VERSION 5.8 ;
BUSBITCHARS "[]" ;
DIVIDERCHAR "/" ;
UNITS
    DATABASE MICRONS 1000 ;
END UNITS

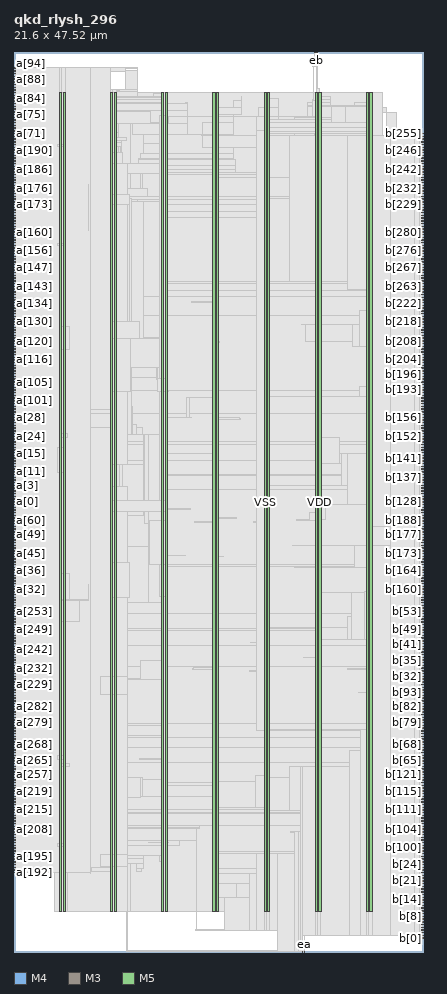
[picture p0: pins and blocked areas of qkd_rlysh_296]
MACRO qkd_rlysh_296
  FOREIGN qkd_rlysh_296 0 0 ;
  CLASS BLOCK ;
  SIZE 21.6 BY 47.52 ;
  PIN a[0]
    DIRECTION INPUT ;
    USE SIGNAL ;
    PORT
      LAYER M4 ;
        RECT  0 23.76 0.084 23.784 ;
    END
  END a[0]
  PIN a[100]
    DIRECTION INPUT ;
    USE SIGNAL ;
    PORT
      LAYER M4 ;
        RECT  0 28.944 0.084 28.968 ;
    END
  END a[100]
  PIN a[101]
    DIRECTION INPUT ;
    USE SIGNAL ;
    PORT
      LAYER M4 ;
        RECT  0 29.088 0.084 29.112 ;
    END
  END a[101]
  PIN a[102]
    DIRECTION INPUT ;
    USE SIGNAL ;
    PORT
      LAYER M4 ;
        RECT  0 29.232 0.084 29.256 ;
    END
  END a[102]
  PIN a[103]
    DIRECTION INPUT ;
    USE SIGNAL ;
    PORT
      LAYER M4 ;
        RECT  0 29.376 0.084 29.4 ;
    END
  END a[103]
  PIN a[104]
    DIRECTION INPUT ;
    USE SIGNAL ;
    PORT
      LAYER M4 ;
        RECT  0 29.52 0.084 29.544 ;
    END
  END a[104]
  PIN a[105]
    DIRECTION INPUT ;
    USE SIGNAL ;
    PORT
      LAYER M4 ;
        RECT  0 29.664 0.084 29.688 ;
    END
  END a[105]
  PIN a[106]
    DIRECTION INPUT ;
    USE SIGNAL ;
    PORT
      LAYER M4 ;
        RECT  0 29.808 0.084 29.832 ;
    END
  END a[106]
  PIN a[107]
    DIRECTION INPUT ;
    USE SIGNAL ;
    PORT
      LAYER M4 ;
        RECT  0 29.952 0.084 29.976 ;
    END
  END a[107]
  PIN a[108]
    DIRECTION INPUT ;
    USE SIGNAL ;
    PORT
      LAYER M4 ;
        RECT  0 30.096 0.084 30.12 ;
    END
  END a[108]
  PIN a[109]
    DIRECTION INPUT ;
    USE SIGNAL ;
    PORT
      LAYER M4 ;
        RECT  0 30.24 0.084 30.264 ;
    END
  END a[109]
  PIN a[10]
    DIRECTION INPUT ;
    USE SIGNAL ;
    PORT
      LAYER M4 ;
        RECT  0 25.2 0.084 25.224 ;
    END
  END a[10]
  PIN a[110]
    DIRECTION INPUT ;
    USE SIGNAL ;
    PORT
      LAYER M4 ;
        RECT  0 30.384 0.084 30.408 ;
    END
  END a[110]
  PIN a[111]
    DIRECTION INPUT ;
    USE SIGNAL ;
    PORT
      LAYER M4 ;
        RECT  0 30.528 0.084 30.552 ;
    END
  END a[111]
  PIN a[112]
    DIRECTION INPUT ;
    USE SIGNAL ;
    PORT
      LAYER M4 ;
        RECT  0 30.672 0.084 30.696 ;
    END
  END a[112]
  PIN a[113]
    DIRECTION INPUT ;
    USE SIGNAL ;
    PORT
      LAYER M4 ;
        RECT  0 30.816 0.084 30.84 ;
    END
  END a[113]
  PIN a[114]
    DIRECTION INPUT ;
    USE SIGNAL ;
    PORT
      LAYER M4 ;
        RECT  0 30.96 0.084 30.984 ;
    END
  END a[114]
  PIN a[115]
    DIRECTION INPUT ;
    USE SIGNAL ;
    PORT
      LAYER M4 ;
        RECT  0 31.104 0.084 31.128 ;
    END
  END a[115]
  PIN a[116]
    DIRECTION INPUT ;
    USE SIGNAL ;
    PORT
      LAYER M4 ;
        RECT  0 31.248 0.084 31.272 ;
    END
  END a[116]
  PIN a[117]
    DIRECTION INPUT ;
    USE SIGNAL ;
    PORT
      LAYER M4 ;
        RECT  0 31.392 0.084 31.416 ;
    END
  END a[117]
  PIN a[118]
    DIRECTION INPUT ;
    USE SIGNAL ;
    PORT
      LAYER M4 ;
        RECT  0 31.536 0.084 31.56 ;
    END
  END a[118]
  PIN a[119]
    DIRECTION INPUT ;
    USE SIGNAL ;
    PORT
      LAYER M4 ;
        RECT  0 31.68 0.084 31.704 ;
    END
  END a[119]
  PIN a[11]
    DIRECTION INPUT ;
    USE SIGNAL ;
    PORT
      LAYER M4 ;
        RECT  0 25.344 0.084 25.368 ;
    END
  END a[11]
  PIN a[120]
    DIRECTION INPUT ;
    USE SIGNAL ;
    PORT
      LAYER M4 ;
        RECT  0 31.824 0.084 31.848 ;
    END
  END a[120]
  PIN a[121]
    DIRECTION INPUT ;
    USE SIGNAL ;
    PORT
      LAYER M4 ;
        RECT  0 31.968 0.084 31.992 ;
    END
  END a[121]
  PIN a[122]
    DIRECTION INPUT ;
    USE SIGNAL ;
    PORT
      LAYER M4 ;
        RECT  0 32.112 0.084 32.136 ;
    END
  END a[122]
  PIN a[123]
    DIRECTION INPUT ;
    USE SIGNAL ;
    PORT
      LAYER M4 ;
        RECT  0 32.256 0.084 32.28 ;
    END
  END a[123]
  PIN a[124]
    DIRECTION INPUT ;
    USE SIGNAL ;
    PORT
      LAYER M4 ;
        RECT  0 32.4 0.084 32.424 ;
    END
  END a[124]
  PIN a[125]
    DIRECTION INPUT ;
    USE SIGNAL ;
    PORT
      LAYER M4 ;
        RECT  0 32.544 0.084 32.568 ;
    END
  END a[125]
  PIN a[126]
    DIRECTION INPUT ;
    USE SIGNAL ;
    PORT
      LAYER M4 ;
        RECT  0 32.688 0.084 32.712 ;
    END
  END a[126]
  PIN a[127]
    DIRECTION INPUT ;
    USE SIGNAL ;
    PORT
      LAYER M4 ;
        RECT  0 32.832 0.084 32.856 ;
    END
  END a[127]
  PIN a[128]
    DIRECTION INPUT ;
    USE SIGNAL ;
    PORT
      LAYER M4 ;
        RECT  0 32.976 0.084 33 ;
    END
  END a[128]
  PIN a[129]
    DIRECTION INPUT ;
    USE SIGNAL ;
    PORT
      LAYER M4 ;
        RECT  0 33.12 0.084 33.144 ;
    END
  END a[129]
  PIN a[12]
    DIRECTION INPUT ;
    USE SIGNAL ;
    PORT
      LAYER M4 ;
        RECT  0 25.488 0.084 25.512 ;
    END
  END a[12]
  PIN a[130]
    DIRECTION INPUT ;
    USE SIGNAL ;
    PORT
      LAYER M4 ;
        RECT  0 33.264 0.084 33.288 ;
    END
  END a[130]
  PIN a[131]
    DIRECTION INPUT ;
    USE SIGNAL ;
    PORT
      LAYER M4 ;
        RECT  0 33.408 0.084 33.432 ;
    END
  END a[131]
  PIN a[132]
    DIRECTION INPUT ;
    USE SIGNAL ;
    PORT
      LAYER M4 ;
        RECT  0 33.552 0.084 33.576 ;
    END
  END a[132]
  PIN a[133]
    DIRECTION INPUT ;
    USE SIGNAL ;
    PORT
      LAYER M4 ;
        RECT  0 33.696 0.084 33.72 ;
    END
  END a[133]
  PIN a[134]
    DIRECTION INPUT ;
    USE SIGNAL ;
    PORT
      LAYER M4 ;
        RECT  0 33.84 0.084 33.864 ;
    END
  END a[134]
  PIN a[135]
    DIRECTION INPUT ;
    USE SIGNAL ;
    PORT
      LAYER M4 ;
        RECT  0 33.984 0.084 34.008 ;
    END
  END a[135]
  PIN a[136]
    DIRECTION INPUT ;
    USE SIGNAL ;
    PORT
      LAYER M4 ;
        RECT  0 34.128 0.084 34.152 ;
    END
  END a[136]
  PIN a[137]
    DIRECTION INPUT ;
    USE SIGNAL ;
    PORT
      LAYER M4 ;
        RECT  0 34.272 0.084 34.296 ;
    END
  END a[137]
  PIN a[138]
    DIRECTION INPUT ;
    USE SIGNAL ;
    PORT
      LAYER M4 ;
        RECT  0 34.416 0.084 34.44 ;
    END
  END a[138]
  PIN a[139]
    DIRECTION INPUT ;
    USE SIGNAL ;
    PORT
      LAYER M4 ;
        RECT  0 34.56 0.084 34.584 ;
    END
  END a[139]
  PIN a[13]
    DIRECTION INPUT ;
    USE SIGNAL ;
    PORT
      LAYER M4 ;
        RECT  0 25.632 0.084 25.656 ;
    END
  END a[13]
  PIN a[140]
    DIRECTION INPUT ;
    USE SIGNAL ;
    PORT
      LAYER M4 ;
        RECT  0 34.704 0.084 34.728 ;
    END
  END a[140]
  PIN a[141]
    DIRECTION INPUT ;
    USE SIGNAL ;
    PORT
      LAYER M4 ;
        RECT  0 34.848 0.084 34.872 ;
    END
  END a[141]
  PIN a[142]
    DIRECTION INPUT ;
    USE SIGNAL ;
    PORT
      LAYER M4 ;
        RECT  0 34.992 0.084 35.016 ;
    END
  END a[142]
  PIN a[143]
    DIRECTION INPUT ;
    USE SIGNAL ;
    PORT
      LAYER M4 ;
        RECT  0 35.136 0.084 35.16 ;
    END
  END a[143]
  PIN a[144]
    DIRECTION INPUT ;
    USE SIGNAL ;
    PORT
      LAYER M4 ;
        RECT  0 35.28 0.084 35.304 ;
    END
  END a[144]
  PIN a[145]
    DIRECTION INPUT ;
    USE SIGNAL ;
    PORT
      LAYER M4 ;
        RECT  0 35.424 0.084 35.448 ;
    END
  END a[145]
  PIN a[146]
    DIRECTION INPUT ;
    USE SIGNAL ;
    PORT
      LAYER M4 ;
        RECT  0 35.568 0.084 35.592 ;
    END
  END a[146]
  PIN a[147]
    DIRECTION INPUT ;
    USE SIGNAL ;
    PORT
      LAYER M4 ;
        RECT  0 35.712 0.084 35.736 ;
    END
  END a[147]
  PIN a[148]
    DIRECTION INPUT ;
    USE SIGNAL ;
    PORT
      LAYER M4 ;
        RECT  0 35.856 0.084 35.88 ;
    END
  END a[148]
  PIN a[149]
    DIRECTION INPUT ;
    USE SIGNAL ;
    PORT
      LAYER M4 ;
        RECT  0 36 0.084 36.024 ;
    END
  END a[149]
  PIN a[14]
    DIRECTION INPUT ;
    USE SIGNAL ;
    PORT
      LAYER M4 ;
        RECT  0 25.776 0.084 25.8 ;
    END
  END a[14]
  PIN a[150]
    DIRECTION INPUT ;
    USE SIGNAL ;
    PORT
      LAYER M4 ;
        RECT  0 36.144 0.084 36.168 ;
    END
  END a[150]
  PIN a[151]
    DIRECTION INPUT ;
    USE SIGNAL ;
    PORT
      LAYER M4 ;
        RECT  0 36.288 0.084 36.312 ;
    END
  END a[151]
  PIN a[152]
    DIRECTION INPUT ;
    USE SIGNAL ;
    PORT
      LAYER M4 ;
        RECT  0 36.432 0.084 36.456 ;
    END
  END a[152]
  PIN a[153]
    DIRECTION INPUT ;
    USE SIGNAL ;
    PORT
      LAYER M4 ;
        RECT  0 36.576 0.084 36.6 ;
    END
  END a[153]
  PIN a[154]
    DIRECTION INPUT ;
    USE SIGNAL ;
    PORT
      LAYER M4 ;
        RECT  0 36.72 0.084 36.744 ;
    END
  END a[154]
  PIN a[155]
    DIRECTION INPUT ;
    USE SIGNAL ;
    PORT
      LAYER M4 ;
        RECT  0 36.864 0.084 36.888 ;
    END
  END a[155]
  PIN a[156]
    DIRECTION INPUT ;
    USE SIGNAL ;
    PORT
      LAYER M4 ;
        RECT  0 37.008 0.084 37.032 ;
    END
  END a[156]
  PIN a[157]
    DIRECTION INPUT ;
    USE SIGNAL ;
    PORT
      LAYER M4 ;
        RECT  0 37.152 0.084 37.176 ;
    END
  END a[157]
  PIN a[158]
    DIRECTION INPUT ;
    USE SIGNAL ;
    PORT
      LAYER M4 ;
        RECT  0 37.296 0.084 37.32 ;
    END
  END a[158]
  PIN a[159]
    DIRECTION INPUT ;
    USE SIGNAL ;
    PORT
      LAYER M4 ;
        RECT  0 37.44 0.084 37.464 ;
    END
  END a[159]
  PIN a[15]
    DIRECTION INPUT ;
    USE SIGNAL ;
    PORT
      LAYER M4 ;
        RECT  0 25.92 0.084 25.944 ;
    END
  END a[15]
  PIN a[160]
    DIRECTION INPUT ;
    USE SIGNAL ;
    PORT
      LAYER M4 ;
        RECT  0 37.584 0.084 37.608 ;
    END
  END a[160]
  PIN a[161]
    DIRECTION INPUT ;
    USE SIGNAL ;
    PORT
      LAYER M4 ;
        RECT  0 37.728 0.084 37.752 ;
    END
  END a[161]
  PIN a[162]
    DIRECTION INPUT ;
    USE SIGNAL ;
    PORT
      LAYER M4 ;
        RECT  0 37.872 0.084 37.896 ;
    END
  END a[162]
  PIN a[163]
    DIRECTION INPUT ;
    USE SIGNAL ;
    PORT
      LAYER M4 ;
        RECT  0 38.016 0.084 38.04 ;
    END
  END a[163]
  PIN a[164]
    DIRECTION INPUT ;
    USE SIGNAL ;
    PORT
      LAYER M4 ;
        RECT  0 38.16 0.084 38.184 ;
    END
  END a[164]
  PIN a[165]
    DIRECTION INPUT ;
    USE SIGNAL ;
    PORT
      LAYER M4 ;
        RECT  0 38.304 0.084 38.328 ;
    END
  END a[165]
  PIN a[166]
    DIRECTION INPUT ;
    USE SIGNAL ;
    PORT
      LAYER M4 ;
        RECT  0 38.448 0.084 38.472 ;
    END
  END a[166]
  PIN a[167]
    DIRECTION INPUT ;
    USE SIGNAL ;
    PORT
      LAYER M4 ;
        RECT  0 38.592 0.084 38.616 ;
    END
  END a[167]
  PIN a[168]
    DIRECTION INPUT ;
    USE SIGNAL ;
    PORT
      LAYER M4 ;
        RECT  0 38.736 0.084 38.76 ;
    END
  END a[168]
  PIN a[169]
    DIRECTION INPUT ;
    USE SIGNAL ;
    PORT
      LAYER M4 ;
        RECT  0 38.88 0.084 38.904 ;
    END
  END a[169]
  PIN a[16]
    DIRECTION INPUT ;
    USE SIGNAL ;
    PORT
      LAYER M4 ;
        RECT  0 26.064 0.084 26.088 ;
    END
  END a[16]
  PIN a[170]
    DIRECTION INPUT ;
    USE SIGNAL ;
    PORT
      LAYER M4 ;
        RECT  0 39.024 0.084 39.048 ;
    END
  END a[170]
  PIN a[171]
    DIRECTION INPUT ;
    USE SIGNAL ;
    PORT
      LAYER M4 ;
        RECT  0 39.168 0.084 39.192 ;
    END
  END a[171]
  PIN a[172]
    DIRECTION INPUT ;
    USE SIGNAL ;
    PORT
      LAYER M4 ;
        RECT  0 39.312 0.084 39.336 ;
    END
  END a[172]
  PIN a[173]
    DIRECTION INPUT ;
    USE SIGNAL ;
    PORT
      LAYER M4 ;
        RECT  0 39.456 0.084 39.48 ;
    END
  END a[173]
  PIN a[174]
    DIRECTION INPUT ;
    USE SIGNAL ;
    PORT
      LAYER M4 ;
        RECT  0 39.6 0.084 39.624 ;
    END
  END a[174]
  PIN a[175]
    DIRECTION INPUT ;
    USE SIGNAL ;
    PORT
      LAYER M4 ;
        RECT  0 39.744 0.084 39.768 ;
    END
  END a[175]
  PIN a[176]
    DIRECTION INPUT ;
    USE SIGNAL ;
    PORT
      LAYER M4 ;
        RECT  0 39.888 0.084 39.912 ;
    END
  END a[176]
  PIN a[177]
    DIRECTION INPUT ;
    USE SIGNAL ;
    PORT
      LAYER M4 ;
        RECT  0 40.032 0.084 40.056 ;
    END
  END a[177]
  PIN a[178]
    DIRECTION INPUT ;
    USE SIGNAL ;
    PORT
      LAYER M4 ;
        RECT  0 40.176 0.084 40.2 ;
    END
  END a[178]
  PIN a[179]
    DIRECTION INPUT ;
    USE SIGNAL ;
    PORT
      LAYER M4 ;
        RECT  0 40.32 0.084 40.344 ;
    END
  END a[179]
  PIN a[17]
    DIRECTION INPUT ;
    USE SIGNAL ;
    PORT
      LAYER M4 ;
        RECT  0 26.208 0.084 26.232 ;
    END
  END a[17]
  PIN a[180]
    DIRECTION INPUT ;
    USE SIGNAL ;
    PORT
      LAYER M4 ;
        RECT  0 40.464 0.084 40.488 ;
    END
  END a[180]
  PIN a[181]
    DIRECTION INPUT ;
    USE SIGNAL ;
    PORT
      LAYER M4 ;
        RECT  0 40.608 0.084 40.632 ;
    END
  END a[181]
  PIN a[182]
    DIRECTION INPUT ;
    USE SIGNAL ;
    PORT
      LAYER M4 ;
        RECT  0 40.752 0.084 40.776 ;
    END
  END a[182]
  PIN a[183]
    DIRECTION INPUT ;
    USE SIGNAL ;
    PORT
      LAYER M4 ;
        RECT  0 40.896 0.084 40.92 ;
    END
  END a[183]
  PIN a[184]
    DIRECTION INPUT ;
    USE SIGNAL ;
    PORT
      LAYER M4 ;
        RECT  0 41.04 0.084 41.064 ;
    END
  END a[184]
  PIN a[185]
    DIRECTION INPUT ;
    USE SIGNAL ;
    PORT
      LAYER M4 ;
        RECT  0 41.184 0.084 41.208 ;
    END
  END a[185]
  PIN a[186]
    DIRECTION INPUT ;
    USE SIGNAL ;
    PORT
      LAYER M4 ;
        RECT  0 41.328 0.084 41.352 ;
    END
  END a[186]
  PIN a[187]
    DIRECTION INPUT ;
    USE SIGNAL ;
    PORT
      LAYER M4 ;
        RECT  0 41.472 0.084 41.496 ;
    END
  END a[187]
  PIN a[188]
    DIRECTION INPUT ;
    USE SIGNAL ;
    PORT
      LAYER M4 ;
        RECT  0 41.616 0.084 41.64 ;
    END
  END a[188]
  PIN a[189]
    DIRECTION INPUT ;
    USE SIGNAL ;
    PORT
      LAYER M4 ;
        RECT  0 41.76 0.084 41.784 ;
    END
  END a[189]
  PIN a[18]
    DIRECTION INPUT ;
    USE SIGNAL ;
    PORT
      LAYER M4 ;
        RECT  0 26.352 0.084 26.376 ;
    END
  END a[18]
  PIN a[190]
    DIRECTION INPUT ;
    USE SIGNAL ;
    PORT
      LAYER M4 ;
        RECT  0 41.904 0.084 41.928 ;
    END
  END a[190]
  PIN a[191]
    DIRECTION INPUT ;
    USE SIGNAL ;
    PORT
      LAYER M4 ;
        RECT  0 42.048 0.084 42.072 ;
    END
  END a[191]
  PIN a[192]
    DIRECTION INPUT ;
    USE SIGNAL ;
    PORT
      LAYER M4 ;
        RECT  0 4.176 0.084 4.2 ;
    END
  END a[192]
  PIN a[193]
    DIRECTION INPUT ;
    USE SIGNAL ;
    PORT
      LAYER M4 ;
        RECT  0 4.32 0.084 4.344 ;
    END
  END a[193]
  PIN a[194]
    DIRECTION INPUT ;
    USE SIGNAL ;
    PORT
      LAYER M4 ;
        RECT  0 4.464 0.084 4.488 ;
    END
  END a[194]
  PIN a[195]
    DIRECTION INPUT ;
    USE SIGNAL ;
    PORT
      LAYER M4 ;
        RECT  0 4.608 0.084 4.632 ;
    END
  END a[195]
  PIN a[196]
    DIRECTION INPUT ;
    USE SIGNAL ;
    PORT
      LAYER M4 ;
        RECT  0 4.752 0.084 4.776 ;
    END
  END a[196]
  PIN a[197]
    DIRECTION INPUT ;
    USE SIGNAL ;
    PORT
      LAYER M4 ;
        RECT  0 4.896 0.084 4.92 ;
    END
  END a[197]
  PIN a[198]
    DIRECTION INPUT ;
    USE SIGNAL ;
    PORT
      LAYER M4 ;
        RECT  0 5.04 0.084 5.064 ;
    END
  END a[198]
  PIN a[199]
    DIRECTION INPUT ;
    USE SIGNAL ;
    PORT
      LAYER M4 ;
        RECT  0 5.184 0.084 5.208 ;
    END
  END a[199]
  PIN a[19]
    DIRECTION INPUT ;
    USE SIGNAL ;
    PORT
      LAYER M4 ;
        RECT  0 26.496 0.084 26.52 ;
    END
  END a[19]
  PIN a[1]
    DIRECTION INPUT ;
    USE SIGNAL ;
    PORT
      LAYER M4 ;
        RECT  0 23.904 0.084 23.928 ;
    END
  END a[1]
  PIN a[200]
    DIRECTION INPUT ;
    USE SIGNAL ;
    PORT
      LAYER M4 ;
        RECT  0 5.328 0.084 5.352 ;
    END
  END a[200]
  PIN a[201]
    DIRECTION INPUT ;
    USE SIGNAL ;
    PORT
      LAYER M4 ;
        RECT  0 5.472 0.084 5.496 ;
    END
  END a[201]
  PIN a[202]
    DIRECTION INPUT ;
    USE SIGNAL ;
    PORT
      LAYER M4 ;
        RECT  0 5.616 0.084 5.64 ;
    END
  END a[202]
  PIN a[203]
    DIRECTION INPUT ;
    USE SIGNAL ;
    PORT
      LAYER M4 ;
        RECT  0 5.76 0.084 5.784 ;
    END
  END a[203]
  PIN a[204]
    DIRECTION INPUT ;
    USE SIGNAL ;
    PORT
      LAYER M4 ;
        RECT  0 5.904 0.084 5.928 ;
    END
  END a[204]
  PIN a[205]
    DIRECTION INPUT ;
    USE SIGNAL ;
    PORT
      LAYER M4 ;
        RECT  0 6.048 0.084 6.072 ;
    END
  END a[205]
  PIN a[206]
    DIRECTION INPUT ;
    USE SIGNAL ;
    PORT
      LAYER M4 ;
        RECT  0 6.192 0.084 6.216 ;
    END
  END a[206]
  PIN a[207]
    DIRECTION INPUT ;
    USE SIGNAL ;
    PORT
      LAYER M4 ;
        RECT  0 6.336 0.084 6.36 ;
    END
  END a[207]
  PIN a[208]
    DIRECTION INPUT ;
    USE SIGNAL ;
    PORT
      LAYER M4 ;
        RECT  0 6.48 0.084 6.504 ;
    END
  END a[208]
  PIN a[209]
    DIRECTION INPUT ;
    USE SIGNAL ;
    PORT
      LAYER M4 ;
        RECT  0 6.624 0.084 6.648 ;
    END
  END a[209]
  PIN a[20]
    DIRECTION INPUT ;
    USE SIGNAL ;
    PORT
      LAYER M4 ;
        RECT  0 26.64 0.084 26.664 ;
    END
  END a[20]
  PIN a[210]
    DIRECTION INPUT ;
    USE SIGNAL ;
    PORT
      LAYER M4 ;
        RECT  0 6.768 0.084 6.792 ;
    END
  END a[210]
  PIN a[211]
    DIRECTION INPUT ;
    USE SIGNAL ;
    PORT
      LAYER M4 ;
        RECT  0 6.912 0.084 6.936 ;
    END
  END a[211]
  PIN a[212]
    DIRECTION INPUT ;
    USE SIGNAL ;
    PORT
      LAYER M4 ;
        RECT  0 7.056 0.084 7.08 ;
    END
  END a[212]
  PIN a[213]
    DIRECTION INPUT ;
    USE SIGNAL ;
    PORT
      LAYER M4 ;
        RECT  0 7.2 0.084 7.224 ;
    END
  END a[213]
  PIN a[214]
    DIRECTION INPUT ;
    USE SIGNAL ;
    PORT
      LAYER M4 ;
        RECT  0 7.344 0.084 7.368 ;
    END
  END a[214]
  PIN a[215]
    DIRECTION INPUT ;
    USE SIGNAL ;
    PORT
      LAYER M4 ;
        RECT  0 7.488 0.084 7.512 ;
    END
  END a[215]
  PIN a[216]
    DIRECTION INPUT ;
    USE SIGNAL ;
    PORT
      LAYER M4 ;
        RECT  0 7.632 0.084 7.656 ;
    END
  END a[216]
  PIN a[217]
    DIRECTION INPUT ;
    USE SIGNAL ;
    PORT
      LAYER M4 ;
        RECT  0 7.776 0.084 7.8 ;
    END
  END a[217]
  PIN a[218]
    DIRECTION INPUT ;
    USE SIGNAL ;
    PORT
      LAYER M4 ;
        RECT  0 7.92 0.084 7.944 ;
    END
  END a[218]
  PIN a[219]
    DIRECTION INPUT ;
    USE SIGNAL ;
    PORT
      LAYER M4 ;
        RECT  0 8.064 0.084 8.088 ;
    END
  END a[219]
  PIN a[21]
    DIRECTION INPUT ;
    USE SIGNAL ;
    PORT
      LAYER M4 ;
        RECT  0 26.784 0.084 26.808 ;
    END
  END a[21]
  PIN a[220]
    DIRECTION INPUT ;
    USE SIGNAL ;
    PORT
      LAYER M4 ;
        RECT  0 8.208 0.084 8.232 ;
    END
  END a[220]
  PIN a[221]
    DIRECTION INPUT ;
    USE SIGNAL ;
    PORT
      LAYER M4 ;
        RECT  0 8.352 0.084 8.376 ;
    END
  END a[221]
  PIN a[222]
    DIRECTION INPUT ;
    USE SIGNAL ;
    PORT
      LAYER M4 ;
        RECT  0 8.496 0.084 8.52 ;
    END
  END a[222]
  PIN a[223]
    DIRECTION INPUT ;
    USE SIGNAL ;
    PORT
      LAYER M4 ;
        RECT  0 8.64 0.084 8.664 ;
    END
  END a[223]
  PIN a[224]
    DIRECTION INPUT ;
    USE SIGNAL ;
    PORT
      LAYER M4 ;
        RECT  0 13.392 0.084 13.416 ;
    END
  END a[224]
  PIN a[225]
    DIRECTION INPUT ;
    USE SIGNAL ;
    PORT
      LAYER M4 ;
        RECT  0 13.536 0.084 13.56 ;
    END
  END a[225]
  PIN a[226]
    DIRECTION INPUT ;
    USE SIGNAL ;
    PORT
      LAYER M4 ;
        RECT  0 13.68 0.084 13.704 ;
    END
  END a[226]
  PIN a[227]
    DIRECTION INPUT ;
    USE SIGNAL ;
    PORT
      LAYER M4 ;
        RECT  0 13.824 0.084 13.848 ;
    END
  END a[227]
  PIN a[228]
    DIRECTION INPUT ;
    USE SIGNAL ;
    PORT
      LAYER M4 ;
        RECT  0 13.968 0.084 13.992 ;
    END
  END a[228]
  PIN a[229]
    DIRECTION INPUT ;
    USE SIGNAL ;
    PORT
      LAYER M4 ;
        RECT  0 14.112 0.084 14.136 ;
    END
  END a[229]
  PIN a[22]
    DIRECTION INPUT ;
    USE SIGNAL ;
    PORT
      LAYER M4 ;
        RECT  0 26.928 0.084 26.952 ;
    END
  END a[22]
  PIN a[230]
    DIRECTION INPUT ;
    USE SIGNAL ;
    PORT
      LAYER M4 ;
        RECT  0 14.256 0.084 14.28 ;
    END
  END a[230]
  PIN a[231]
    DIRECTION INPUT ;
    USE SIGNAL ;
    PORT
      LAYER M4 ;
        RECT  0 14.4 0.084 14.424 ;
    END
  END a[231]
  PIN a[232]
    DIRECTION INPUT ;
    USE SIGNAL ;
    PORT
      LAYER M4 ;
        RECT  0 14.544 0.084 14.568 ;
    END
  END a[232]
  PIN a[233]
    DIRECTION INPUT ;
    USE SIGNAL ;
    PORT
      LAYER M4 ;
        RECT  0 14.688 0.084 14.712 ;
    END
  END a[233]
  PIN a[234]
    DIRECTION INPUT ;
    USE SIGNAL ;
    PORT
      LAYER M4 ;
        RECT  0 14.832 0.084 14.856 ;
    END
  END a[234]
  PIN a[235]
    DIRECTION INPUT ;
    USE SIGNAL ;
    PORT
      LAYER M4 ;
        RECT  0 14.976 0.084 15 ;
    END
  END a[235]
  PIN a[236]
    DIRECTION INPUT ;
    USE SIGNAL ;
    PORT
      LAYER M4 ;
        RECT  0 15.12 0.084 15.144 ;
    END
  END a[236]
  PIN a[237]
    DIRECTION INPUT ;
    USE SIGNAL ;
    PORT
      LAYER M4 ;
        RECT  0 15.264 0.084 15.288 ;
    END
  END a[237]
  PIN a[238]
    DIRECTION INPUT ;
    USE SIGNAL ;
    PORT
      LAYER M4 ;
        RECT  0 15.408 0.084 15.432 ;
    END
  END a[238]
  PIN a[239]
    DIRECTION INPUT ;
    USE SIGNAL ;
    PORT
      LAYER M4 ;
        RECT  0 15.552 0.084 15.576 ;
    END
  END a[239]
  PIN a[23]
    DIRECTION INPUT ;
    USE SIGNAL ;
    PORT
      LAYER M4 ;
        RECT  0 27.072 0.084 27.096 ;
    END
  END a[23]
  PIN a[240]
    DIRECTION INPUT ;
    USE SIGNAL ;
    PORT
      LAYER M4 ;
        RECT  0 15.696 0.084 15.72 ;
    END
  END a[240]
  PIN a[241]
    DIRECTION INPUT ;
    USE SIGNAL ;
    PORT
      LAYER M4 ;
        RECT  0 15.84 0.084 15.864 ;
    END
  END a[241]
  PIN a[242]
    DIRECTION INPUT ;
    USE SIGNAL ;
    PORT
      LAYER M4 ;
        RECT  0 15.984 0.084 16.008 ;
    END
  END a[242]
  PIN a[243]
    DIRECTION INPUT ;
    USE SIGNAL ;
    PORT
      LAYER M4 ;
        RECT  0 16.128 0.084 16.152 ;
    END
  END a[243]
  PIN a[244]
    DIRECTION INPUT ;
    USE SIGNAL ;
    PORT
      LAYER M4 ;
        RECT  0 16.272 0.084 16.296 ;
    END
  END a[244]
  PIN a[245]
    DIRECTION INPUT ;
    USE SIGNAL ;
    PORT
      LAYER M4 ;
        RECT  0 16.416 0.084 16.44 ;
    END
  END a[245]
  PIN a[246]
    DIRECTION INPUT ;
    USE SIGNAL ;
    PORT
      LAYER M4 ;
        RECT  0 16.56 0.084 16.584 ;
    END
  END a[246]
  PIN a[247]
    DIRECTION INPUT ;
    USE SIGNAL ;
    PORT
      LAYER M4 ;
        RECT  0 16.704 0.084 16.728 ;
    END
  END a[247]
  PIN a[248]
    DIRECTION INPUT ;
    USE SIGNAL ;
    PORT
      LAYER M4 ;
        RECT  0 16.848 0.084 16.872 ;
    END
  END a[248]
  PIN a[249]
    DIRECTION INPUT ;
    USE SIGNAL ;
    PORT
      LAYER M4 ;
        RECT  0 16.992 0.084 17.016 ;
    END
  END a[249]
  PIN a[24]
    DIRECTION INPUT ;
    USE SIGNAL ;
    PORT
      LAYER M4 ;
        RECT  0 27.216 0.084 27.24 ;
    END
  END a[24]
  PIN a[250]
    DIRECTION INPUT ;
    USE SIGNAL ;
    PORT
      LAYER M4 ;
        RECT  0 17.136 0.084 17.16 ;
    END
  END a[250]
  PIN a[251]
    DIRECTION INPUT ;
    USE SIGNAL ;
    PORT
      LAYER M4 ;
        RECT  0 17.28 0.084 17.304 ;
    END
  END a[251]
  PIN a[252]
    DIRECTION INPUT ;
    USE SIGNAL ;
    PORT
      LAYER M4 ;
        RECT  0 17.424 0.084 17.448 ;
    END
  END a[252]
  PIN a[253]
    DIRECTION INPUT ;
    USE SIGNAL ;
    PORT
      LAYER M4 ;
        RECT  0 17.568 0.084 17.592 ;
    END
  END a[253]
  PIN a[254]
    DIRECTION INPUT ;
    USE SIGNAL ;
    PORT
      LAYER M4 ;
        RECT  0 17.712 0.084 17.736 ;
    END
  END a[254]
  PIN a[255]
    DIRECTION INPUT ;
    USE SIGNAL ;
    PORT
      LAYER M4 ;
        RECT  0 17.856 0.084 17.88 ;
    END
  END a[255]
  PIN a[256]
    DIRECTION INPUT ;
    USE SIGNAL ;
    PORT
      LAYER M4 ;
        RECT  0 8.784 0.084 8.808 ;
    END
  END a[256]
  PIN a[257]
    DIRECTION INPUT ;
    USE SIGNAL ;
    PORT
      LAYER M4 ;
        RECT  0 8.928 0.084 8.952 ;
    END
  END a[257]
  PIN a[258]
    DIRECTION INPUT ;
    USE SIGNAL ;
    PORT
      LAYER M4 ;
        RECT  0 9.072 0.084 9.096 ;
    END
  END a[258]
  PIN a[259]
    DIRECTION INPUT ;
    USE SIGNAL ;
    PORT
      LAYER M4 ;
        RECT  0 9.216 0.084 9.24 ;
    END
  END a[259]
  PIN a[25]
    DIRECTION INPUT ;
    USE SIGNAL ;
    PORT
      LAYER M4 ;
        RECT  0 27.36 0.084 27.384 ;
    END
  END a[25]
  PIN a[260]
    DIRECTION INPUT ;
    USE SIGNAL ;
    PORT
      LAYER M4 ;
        RECT  0 9.36 0.084 9.384 ;
    END
  END a[260]
  PIN a[261]
    DIRECTION INPUT ;
    USE SIGNAL ;
    PORT
      LAYER M4 ;
        RECT  0 9.504 0.084 9.528 ;
    END
  END a[261]
  PIN a[262]
    DIRECTION INPUT ;
    USE SIGNAL ;
    PORT
      LAYER M4 ;
        RECT  0 9.648 0.084 9.672 ;
    END
  END a[262]
  PIN a[263]
    DIRECTION INPUT ;
    USE SIGNAL ;
    PORT
      LAYER M4 ;
        RECT  0 9.792 0.084 9.816 ;
    END
  END a[263]
  PIN a[264]
    DIRECTION INPUT ;
    USE SIGNAL ;
    PORT
      LAYER M4 ;
        RECT  0 9.936 0.084 9.96 ;
    END
  END a[264]
  PIN a[265]
    DIRECTION INPUT ;
    USE SIGNAL ;
    PORT
      LAYER M4 ;
        RECT  0 10.08 0.084 10.104 ;
    END
  END a[265]
  PIN a[266]
    DIRECTION INPUT ;
    USE SIGNAL ;
    PORT
      LAYER M4 ;
        RECT  0 10.224 0.084 10.248 ;
    END
  END a[266]
  PIN a[267]
    DIRECTION INPUT ;
    USE SIGNAL ;
    PORT
      LAYER M4 ;
        RECT  0 10.368 0.084 10.392 ;
    END
  END a[267]
  PIN a[268]
    DIRECTION INPUT ;
    USE SIGNAL ;
    PORT
      LAYER M4 ;
        RECT  0 10.512 0.084 10.536 ;
    END
  END a[268]
  PIN a[269]
    DIRECTION INPUT ;
    USE SIGNAL ;
    PORT
      LAYER M4 ;
        RECT  0 10.656 0.084 10.68 ;
    END
  END a[269]
  PIN a[26]
    DIRECTION INPUT ;
    USE SIGNAL ;
    PORT
      LAYER M4 ;
        RECT  0 27.504 0.084 27.528 ;
    END
  END a[26]
  PIN a[270]
    DIRECTION INPUT ;
    USE SIGNAL ;
    PORT
      LAYER M4 ;
        RECT  0 10.8 0.084 10.824 ;
    END
  END a[270]
  PIN a[271]
    DIRECTION INPUT ;
    USE SIGNAL ;
    PORT
      LAYER M4 ;
        RECT  0 10.944 0.084 10.968 ;
    END
  END a[271]
  PIN a[272]
    DIRECTION INPUT ;
    USE SIGNAL ;
    PORT
      LAYER M4 ;
        RECT  0 11.088 0.084 11.112 ;
    END
  END a[272]
  PIN a[273]
    DIRECTION INPUT ;
    USE SIGNAL ;
    PORT
      LAYER M4 ;
        RECT  0 11.232 0.084 11.256 ;
    END
  END a[273]
  PIN a[274]
    DIRECTION INPUT ;
    USE SIGNAL ;
    PORT
      LAYER M4 ;
        RECT  0 11.376 0.084 11.4 ;
    END
  END a[274]
  PIN a[275]
    DIRECTION INPUT ;
    USE SIGNAL ;
    PORT
      LAYER M4 ;
        RECT  0 11.52 0.084 11.544 ;
    END
  END a[275]
  PIN a[276]
    DIRECTION INPUT ;
    USE SIGNAL ;
    PORT
      LAYER M4 ;
        RECT  0 11.664 0.084 11.688 ;
    END
  END a[276]
  PIN a[277]
    DIRECTION INPUT ;
    USE SIGNAL ;
    PORT
      LAYER M4 ;
        RECT  0 11.808 0.084 11.832 ;
    END
  END a[277]
  PIN a[278]
    DIRECTION INPUT ;
    USE SIGNAL ;
    PORT
      LAYER M4 ;
        RECT  0 11.952 0.084 11.976 ;
    END
  END a[278]
  PIN a[279]
    DIRECTION INPUT ;
    USE SIGNAL ;
    PORT
      LAYER M4 ;
        RECT  0 12.096 0.084 12.12 ;
    END
  END a[279]
  PIN a[27]
    DIRECTION INPUT ;
    USE SIGNAL ;
    PORT
      LAYER M4 ;
        RECT  0 27.648 0.084 27.672 ;
    END
  END a[27]
  PIN a[280]
    DIRECTION INPUT ;
    USE SIGNAL ;
    PORT
      LAYER M4 ;
        RECT  0 12.24 0.084 12.264 ;
    END
  END a[280]
  PIN a[281]
    DIRECTION INPUT ;
    USE SIGNAL ;
    PORT
      LAYER M4 ;
        RECT  0 12.384 0.084 12.408 ;
    END
  END a[281]
  PIN a[282]
    DIRECTION INPUT ;
    USE SIGNAL ;
    PORT
      LAYER M4 ;
        RECT  0 12.528 0.084 12.552 ;
    END
  END a[282]
  PIN a[283]
    DIRECTION INPUT ;
    USE SIGNAL ;
    PORT
      LAYER M4 ;
        RECT  0 12.672 0.084 12.696 ;
    END
  END a[283]
  PIN a[284]
    DIRECTION INPUT ;
    USE SIGNAL ;
    PORT
      LAYER M4 ;
        RECT  0 12.816 0.084 12.84 ;
    END
  END a[284]
  PIN a[285]
    DIRECTION INPUT ;
    USE SIGNAL ;
    PORT
      LAYER M4 ;
        RECT  0 12.96 0.084 12.984 ;
    END
  END a[285]
  PIN a[286]
    DIRECTION INPUT ;
    USE SIGNAL ;
    PORT
      LAYER M4 ;
        RECT  0 13.104 0.084 13.128 ;
    END
  END a[286]
  PIN a[287]
    DIRECTION INPUT ;
    USE SIGNAL ;
    PORT
      LAYER M4 ;
        RECT  0 13.248 0.084 13.272 ;
    END
  END a[287]
  PIN a[288]
    DIRECTION INPUT ;
    USE SIGNAL ;
    PORT
      LAYER M4 ;
        RECT  0 18 0.084 18.024 ;
    END
  END a[288]
  PIN a[289]
    DIRECTION INPUT ;
    USE SIGNAL ;
    PORT
      LAYER M4 ;
        RECT  0 18.144 0.084 18.168 ;
    END
  END a[289]
  PIN a[28]
    DIRECTION INPUT ;
    USE SIGNAL ;
    PORT
      LAYER M4 ;
        RECT  0 27.792 0.084 27.816 ;
    END
  END a[28]
  PIN a[290]
    DIRECTION INPUT ;
    USE SIGNAL ;
    PORT
      LAYER M4 ;
        RECT  0 18.288 0.084 18.312 ;
    END
  END a[290]
  PIN a[291]
    DIRECTION INPUT ;
    USE SIGNAL ;
    PORT
      LAYER M4 ;
        RECT  0 18.432 0.084 18.456 ;
    END
  END a[291]
  PIN a[292]
    DIRECTION INPUT ;
    USE SIGNAL ;
    PORT
      LAYER M4 ;
        RECT  0 18.576 0.084 18.6 ;
    END
  END a[292]
  PIN a[293]
    DIRECTION INPUT ;
    USE SIGNAL ;
    PORT
      LAYER M4 ;
        RECT  0 18.72 0.084 18.744 ;
    END
  END a[293]
  PIN a[294]
    DIRECTION INPUT ;
    USE SIGNAL ;
    PORT
      LAYER M4 ;
        RECT  0 18.864 0.084 18.888 ;
    END
  END a[294]
  PIN a[295]
    DIRECTION INPUT ;
    USE SIGNAL ;
    PORT
      LAYER M4 ;
        RECT  0 19.008 0.084 19.032 ;
    END
  END a[295]
  PIN a[29]
    DIRECTION INPUT ;
    USE SIGNAL ;
    PORT
      LAYER M4 ;
        RECT  0 27.936 0.084 27.96 ;
    END
  END a[29]
  PIN a[2]
    DIRECTION INPUT ;
    USE SIGNAL ;
    PORT
      LAYER M4 ;
        RECT  0 24.048 0.084 24.072 ;
    END
  END a[2]
  PIN a[30]
    DIRECTION INPUT ;
    USE SIGNAL ;
    PORT
      LAYER M4 ;
        RECT  0 28.08 0.084 28.104 ;
    END
  END a[30]
  PIN a[31]
    DIRECTION INPUT ;
    USE SIGNAL ;
    PORT
      LAYER M4 ;
        RECT  0 28.224 0.084 28.248 ;
    END
  END a[31]
  PIN a[32]
    DIRECTION INPUT ;
    USE SIGNAL ;
    PORT
      LAYER M4 ;
        RECT  0 19.152 0.084 19.176 ;
    END
  END a[32]
  PIN a[33]
    DIRECTION INPUT ;
    USE SIGNAL ;
    PORT
      LAYER M4 ;
        RECT  0 19.296 0.084 19.32 ;
    END
  END a[33]
  PIN a[34]
    DIRECTION INPUT ;
    USE SIGNAL ;
    PORT
      LAYER M4 ;
        RECT  0 19.44 0.084 19.464 ;
    END
  END a[34]
  PIN a[35]
    DIRECTION INPUT ;
    USE SIGNAL ;
    PORT
      LAYER M4 ;
        RECT  0 19.584 0.084 19.608 ;
    END
  END a[35]
  PIN a[36]
    DIRECTION INPUT ;
    USE SIGNAL ;
    PORT
      LAYER M4 ;
        RECT  0 19.728 0.084 19.752 ;
    END
  END a[36]
  PIN a[37]
    DIRECTION INPUT ;
    USE SIGNAL ;
    PORT
      LAYER M4 ;
        RECT  0 19.872 0.084 19.896 ;
    END
  END a[37]
  PIN a[38]
    DIRECTION INPUT ;
    USE SIGNAL ;
    PORT
      LAYER M4 ;
        RECT  0 20.016 0.084 20.04 ;
    END
  END a[38]
  PIN a[39]
    DIRECTION INPUT ;
    USE SIGNAL ;
    PORT
      LAYER M4 ;
        RECT  0 20.16 0.084 20.184 ;
    END
  END a[39]
  PIN a[3]
    DIRECTION INPUT ;
    USE SIGNAL ;
    PORT
      LAYER M4 ;
        RECT  0 24.192 0.084 24.216 ;
    END
  END a[3]
  PIN a[40]
    DIRECTION INPUT ;
    USE SIGNAL ;
    PORT
      LAYER M4 ;
        RECT  0 20.304 0.084 20.328 ;
    END
  END a[40]
  PIN a[41]
    DIRECTION INPUT ;
    USE SIGNAL ;
    PORT
      LAYER M4 ;
        RECT  0 20.448 0.084 20.472 ;
    END
  END a[41]
  PIN a[42]
    DIRECTION INPUT ;
    USE SIGNAL ;
    PORT
      LAYER M4 ;
        RECT  0 20.592 0.084 20.616 ;
    END
  END a[42]
  PIN a[43]
    DIRECTION INPUT ;
    USE SIGNAL ;
    PORT
      LAYER M4 ;
        RECT  0 20.736 0.084 20.76 ;
    END
  END a[43]
  PIN a[44]
    DIRECTION INPUT ;
    USE SIGNAL ;
    PORT
      LAYER M4 ;
        RECT  0 20.88 0.084 20.904 ;
    END
  END a[44]
  PIN a[45]
    DIRECTION INPUT ;
    USE SIGNAL ;
    PORT
      LAYER M4 ;
        RECT  0 21.024 0.084 21.048 ;
    END
  END a[45]
  PIN a[46]
    DIRECTION INPUT ;
    USE SIGNAL ;
    PORT
      LAYER M4 ;
        RECT  0 21.168 0.084 21.192 ;
    END
  END a[46]
  PIN a[47]
    DIRECTION INPUT ;
    USE SIGNAL ;
    PORT
      LAYER M4 ;
        RECT  0 21.312 0.084 21.336 ;
    END
  END a[47]
  PIN a[48]
    DIRECTION INPUT ;
    USE SIGNAL ;
    PORT
      LAYER M4 ;
        RECT  0 21.456 0.084 21.48 ;
    END
  END a[48]
  PIN a[49]
    DIRECTION INPUT ;
    USE SIGNAL ;
    PORT
      LAYER M4 ;
        RECT  0 21.6 0.084 21.624 ;
    END
  END a[49]
  PIN a[4]
    DIRECTION INPUT ;
    USE SIGNAL ;
    PORT
      LAYER M4 ;
        RECT  0 24.336 0.084 24.36 ;
    END
  END a[4]
  PIN a[50]
    DIRECTION INPUT ;
    USE SIGNAL ;
    PORT
      LAYER M4 ;
        RECT  0 21.744 0.084 21.768 ;
    END
  END a[50]
  PIN a[51]
    DIRECTION INPUT ;
    USE SIGNAL ;
    PORT
      LAYER M4 ;
        RECT  0 21.888 0.084 21.912 ;
    END
  END a[51]
  PIN a[52]
    DIRECTION INPUT ;
    USE SIGNAL ;
    PORT
      LAYER M4 ;
        RECT  0 22.032 0.084 22.056 ;
    END
  END a[52]
  PIN a[53]
    DIRECTION INPUT ;
    USE SIGNAL ;
    PORT
      LAYER M4 ;
        RECT  0 22.176 0.084 22.2 ;
    END
  END a[53]
  PIN a[54]
    DIRECTION INPUT ;
    USE SIGNAL ;
    PORT
      LAYER M4 ;
        RECT  0 22.32 0.084 22.344 ;
    END
  END a[54]
  PIN a[55]
    DIRECTION INPUT ;
    USE SIGNAL ;
    PORT
      LAYER M4 ;
        RECT  0 22.464 0.084 22.488 ;
    END
  END a[55]
  PIN a[56]
    DIRECTION INPUT ;
    USE SIGNAL ;
    PORT
      LAYER M4 ;
        RECT  0 22.608 0.084 22.632 ;
    END
  END a[56]
  PIN a[57]
    DIRECTION INPUT ;
    USE SIGNAL ;
    PORT
      LAYER M4 ;
        RECT  0 22.752 0.084 22.776 ;
    END
  END a[57]
  PIN a[58]
    DIRECTION INPUT ;
    USE SIGNAL ;
    PORT
      LAYER M4 ;
        RECT  0 22.896 0.084 22.92 ;
    END
  END a[58]
  PIN a[59]
    DIRECTION INPUT ;
    USE SIGNAL ;
    PORT
      LAYER M4 ;
        RECT  0 23.04 0.084 23.064 ;
    END
  END a[59]
  PIN a[5]
    DIRECTION INPUT ;
    USE SIGNAL ;
    PORT
      LAYER M4 ;
        RECT  0 24.48 0.084 24.504 ;
    END
  END a[5]
  PIN a[60]
    DIRECTION INPUT ;
    USE SIGNAL ;
    PORT
      LAYER M4 ;
        RECT  0 23.184 0.084 23.208 ;
    END
  END a[60]
  PIN a[61]
    DIRECTION INPUT ;
    USE SIGNAL ;
    PORT
      LAYER M4 ;
        RECT  0 23.328 0.084 23.352 ;
    END
  END a[61]
  PIN a[62]
    DIRECTION INPUT ;
    USE SIGNAL ;
    PORT
      LAYER M4 ;
        RECT  0 23.472 0.084 23.496 ;
    END
  END a[62]
  PIN a[63]
    DIRECTION INPUT ;
    USE SIGNAL ;
    PORT
      LAYER M4 ;
        RECT  0 23.616 0.084 23.64 ;
    END
  END a[63]
  PIN a[64]
    DIRECTION INPUT ;
    USE SIGNAL ;
    PORT
      LAYER M4 ;
        RECT  0 42.192 0.084 42.216 ;
    END
  END a[64]
  PIN a[65]
    DIRECTION INPUT ;
    USE SIGNAL ;
    PORT
      LAYER M4 ;
        RECT  0 42.336 0.084 42.36 ;
    END
  END a[65]
  PIN a[66]
    DIRECTION INPUT ;
    USE SIGNAL ;
    PORT
      LAYER M4 ;
        RECT  0 42.48 0.084 42.504 ;
    END
  END a[66]
  PIN a[67]
    DIRECTION INPUT ;
    USE SIGNAL ;
    PORT
      LAYER M4 ;
        RECT  0 42.624 0.084 42.648 ;
    END
  END a[67]
  PIN a[68]
    DIRECTION INPUT ;
    USE SIGNAL ;
    PORT
      LAYER M4 ;
        RECT  0 42.768 0.084 42.792 ;
    END
  END a[68]
  PIN a[69]
    DIRECTION INPUT ;
    USE SIGNAL ;
    PORT
      LAYER M4 ;
        RECT  0 42.912 0.084 42.936 ;
    END
  END a[69]
  PIN a[6]
    DIRECTION INPUT ;
    USE SIGNAL ;
    PORT
      LAYER M4 ;
        RECT  0 24.624 0.084 24.648 ;
    END
  END a[6]
  PIN a[70]
    DIRECTION INPUT ;
    USE SIGNAL ;
    PORT
      LAYER M4 ;
        RECT  0 43.056 0.084 43.08 ;
    END
  END a[70]
  PIN a[71]
    DIRECTION INPUT ;
    USE SIGNAL ;
    PORT
      LAYER M4 ;
        RECT  0 43.2 0.084 43.224 ;
    END
  END a[71]
  PIN a[72]
    DIRECTION INPUT ;
    USE SIGNAL ;
    PORT
      LAYER M4 ;
        RECT  0 43.344 0.084 43.368 ;
    END
  END a[72]
  PIN a[73]
    DIRECTION INPUT ;
    USE SIGNAL ;
    PORT
      LAYER M4 ;
        RECT  0 43.488 0.084 43.512 ;
    END
  END a[73]
  PIN a[74]
    DIRECTION INPUT ;
    USE SIGNAL ;
    PORT
      LAYER M4 ;
        RECT  0 43.632 0.084 43.656 ;
    END
  END a[74]
  PIN a[75]
    DIRECTION INPUT ;
    USE SIGNAL ;
    PORT
      LAYER M4 ;
        RECT  0 43.776 0.084 43.8 ;
    END
  END a[75]
  PIN a[76]
    DIRECTION INPUT ;
    USE SIGNAL ;
    PORT
      LAYER M4 ;
        RECT  0 43.92 0.084 43.944 ;
    END
  END a[76]
  PIN a[77]
    DIRECTION INPUT ;
    USE SIGNAL ;
    PORT
      LAYER M4 ;
        RECT  0 44.064 0.084 44.088 ;
    END
  END a[77]
  PIN a[78]
    DIRECTION INPUT ;
    USE SIGNAL ;
    PORT
      LAYER M4 ;
        RECT  0 44.208 0.084 44.232 ;
    END
  END a[78]
  PIN a[79]
    DIRECTION INPUT ;
    USE SIGNAL ;
    PORT
      LAYER M4 ;
        RECT  0 44.352 0.084 44.376 ;
    END
  END a[79]
  PIN a[7]
    DIRECTION INPUT ;
    USE SIGNAL ;
    PORT
      LAYER M4 ;
        RECT  0 24.768 0.084 24.792 ;
    END
  END a[7]
  PIN a[80]
    DIRECTION INPUT ;
    USE SIGNAL ;
    PORT
      LAYER M4 ;
        RECT  0 44.496 0.084 44.52 ;
    END
  END a[80]
  PIN a[81]
    DIRECTION INPUT ;
    USE SIGNAL ;
    PORT
      LAYER M4 ;
        RECT  0 44.64 0.084 44.664 ;
    END
  END a[81]
  PIN a[82]
    DIRECTION INPUT ;
    USE SIGNAL ;
    PORT
      LAYER M4 ;
        RECT  0 44.784 0.084 44.808 ;
    END
  END a[82]
  PIN a[83]
    DIRECTION INPUT ;
    USE SIGNAL ;
    PORT
      LAYER M4 ;
        RECT  0 44.928 0.084 44.952 ;
    END
  END a[83]
  PIN a[84]
    DIRECTION INPUT ;
    USE SIGNAL ;
    PORT
      LAYER M4 ;
        RECT  0 45.072 0.084 45.096 ;
    END
  END a[84]
  PIN a[85]
    DIRECTION INPUT ;
    USE SIGNAL ;
    PORT
      LAYER M4 ;
        RECT  0 45.216 0.084 45.24 ;
    END
  END a[85]
  PIN a[86]
    DIRECTION INPUT ;
    USE SIGNAL ;
    PORT
      LAYER M4 ;
        RECT  0 45.36 0.084 45.384 ;
    END
  END a[86]
  PIN a[87]
    DIRECTION INPUT ;
    USE SIGNAL ;
    PORT
      LAYER M4 ;
        RECT  0 45.504 0.084 45.528 ;
    END
  END a[87]
  PIN a[88]
    DIRECTION INPUT ;
    USE SIGNAL ;
    PORT
      LAYER M4 ;
        RECT  0 45.648 0.084 45.672 ;
    END
  END a[88]
  PIN a[89]
    DIRECTION INPUT ;
    USE SIGNAL ;
    PORT
      LAYER M4 ;
        RECT  0 45.792 0.084 45.816 ;
    END
  END a[89]
  PIN a[8]
    DIRECTION INPUT ;
    USE SIGNAL ;
    PORT
      LAYER M4 ;
        RECT  0 24.912 0.084 24.936 ;
    END
  END a[8]
  PIN a[90]
    DIRECTION INPUT ;
    USE SIGNAL ;
    PORT
      LAYER M4 ;
        RECT  0 45.936 0.084 45.96 ;
    END
  END a[90]
  PIN a[91]
    DIRECTION INPUT ;
    USE SIGNAL ;
    PORT
      LAYER M4 ;
        RECT  0 46.08 0.084 46.104 ;
    END
  END a[91]
  PIN a[92]
    DIRECTION INPUT ;
    USE SIGNAL ;
    PORT
      LAYER M4 ;
        RECT  0 46.224 0.084 46.248 ;
    END
  END a[92]
  PIN a[93]
    DIRECTION INPUT ;
    USE SIGNAL ;
    PORT
      LAYER M4 ;
        RECT  0 46.368 0.084 46.392 ;
    END
  END a[93]
  PIN a[94]
    DIRECTION INPUT ;
    USE SIGNAL ;
    PORT
      LAYER M4 ;
        RECT  0 46.512 0.084 46.536 ;
    END
  END a[94]
  PIN a[95]
    DIRECTION INPUT ;
    USE SIGNAL ;
    PORT
      LAYER M4 ;
        RECT  0 46.656 0.084 46.68 ;
    END
  END a[95]
  PIN a[96]
    DIRECTION INPUT ;
    USE SIGNAL ;
    PORT
      LAYER M4 ;
        RECT  0 28.368 0.084 28.392 ;
    END
  END a[96]
  PIN a[97]
    DIRECTION INPUT ;
    USE SIGNAL ;
    PORT
      LAYER M4 ;
        RECT  0 28.512 0.084 28.536 ;
    END
  END a[97]
  PIN a[98]
    DIRECTION INPUT ;
    USE SIGNAL ;
    PORT
      LAYER M4 ;
        RECT  0 28.656 0.084 28.68 ;
    END
  END a[98]
  PIN a[99]
    DIRECTION INPUT ;
    USE SIGNAL ;
    PORT
      LAYER M4 ;
        RECT  0 28.8 0.084 28.824 ;
    END
  END a[99]
  PIN a[9]
    DIRECTION INPUT ;
    USE SIGNAL ;
    PORT
      LAYER M4 ;
        RECT  0 25.056 0.084 25.08 ;
    END
  END a[9]
  PIN b[0]
    DIRECTION OUTPUT ;
    USE SIGNAL ;
    PORT
      LAYER M4 ;
        RECT  21.516 0.72 21.6 0.744 ;
    END
  END b[0]
  PIN b[100]
    DIRECTION OUTPUT ;
    USE SIGNAL ;
    PORT
      LAYER M4 ;
        RECT  21.516 5.904 21.6 5.928 ;
    END
  END b[100]
  PIN b[101]
    DIRECTION OUTPUT ;
    USE SIGNAL ;
    PORT
      LAYER M4 ;
        RECT  21.516 6.048 21.6 6.072 ;
    END
  END b[101]
  PIN b[102]
    DIRECTION OUTPUT ;
    USE SIGNAL ;
    PORT
      LAYER M4 ;
        RECT  21.516 6.192 21.6 6.216 ;
    END
  END b[102]
  PIN b[103]
    DIRECTION OUTPUT ;
    USE SIGNAL ;
    PORT
      LAYER M4 ;
        RECT  21.516 6.336 21.6 6.36 ;
    END
  END b[103]
  PIN b[104]
    DIRECTION OUTPUT ;
    USE SIGNAL ;
    PORT
      LAYER M4 ;
        RECT  21.516 6.48 21.6 6.504 ;
    END
  END b[104]
  PIN b[105]
    DIRECTION OUTPUT ;
    USE SIGNAL ;
    PORT
      LAYER M4 ;
        RECT  21.516 6.624 21.6 6.648 ;
    END
  END b[105]
  PIN b[106]
    DIRECTION OUTPUT ;
    USE SIGNAL ;
    PORT
      LAYER M4 ;
        RECT  21.516 6.768 21.6 6.792 ;
    END
  END b[106]
  PIN b[107]
    DIRECTION OUTPUT ;
    USE SIGNAL ;
    PORT
      LAYER M4 ;
        RECT  21.516 6.912 21.6 6.936 ;
    END
  END b[107]
  PIN b[108]
    DIRECTION OUTPUT ;
    USE SIGNAL ;
    PORT
      LAYER M4 ;
        RECT  21.516 7.056 21.6 7.08 ;
    END
  END b[108]
  PIN b[109]
    DIRECTION OUTPUT ;
    USE SIGNAL ;
    PORT
      LAYER M4 ;
        RECT  21.516 7.2 21.6 7.224 ;
    END
  END b[109]
  PIN b[10]
    DIRECTION OUTPUT ;
    USE SIGNAL ;
    PORT
      LAYER M4 ;
        RECT  21.516 2.16 21.6 2.184 ;
    END
  END b[10]
  PIN b[110]
    DIRECTION OUTPUT ;
    USE SIGNAL ;
    PORT
      LAYER M4 ;
        RECT  21.516 7.344 21.6 7.368 ;
    END
  END b[110]
  PIN b[111]
    DIRECTION OUTPUT ;
    USE SIGNAL ;
    PORT
      LAYER M4 ;
        RECT  21.516 7.488 21.6 7.512 ;
    END
  END b[111]
  PIN b[112]
    DIRECTION OUTPUT ;
    USE SIGNAL ;
    PORT
      LAYER M4 ;
        RECT  21.516 7.632 21.6 7.656 ;
    END
  END b[112]
  PIN b[113]
    DIRECTION OUTPUT ;
    USE SIGNAL ;
    PORT
      LAYER M4 ;
        RECT  21.516 7.776 21.6 7.8 ;
    END
  END b[113]
  PIN b[114]
    DIRECTION OUTPUT ;
    USE SIGNAL ;
    PORT
      LAYER M4 ;
        RECT  21.516 7.92 21.6 7.944 ;
    END
  END b[114]
  PIN b[115]
    DIRECTION OUTPUT ;
    USE SIGNAL ;
    PORT
      LAYER M4 ;
        RECT  21.516 8.064 21.6 8.088 ;
    END
  END b[115]
  PIN b[116]
    DIRECTION OUTPUT ;
    USE SIGNAL ;
    PORT
      LAYER M4 ;
        RECT  21.516 8.208 21.6 8.232 ;
    END
  END b[116]
  PIN b[117]
    DIRECTION OUTPUT ;
    USE SIGNAL ;
    PORT
      LAYER M4 ;
        RECT  21.516 8.352 21.6 8.376 ;
    END
  END b[117]
  PIN b[118]
    DIRECTION OUTPUT ;
    USE SIGNAL ;
    PORT
      LAYER M4 ;
        RECT  21.516 8.496 21.6 8.52 ;
    END
  END b[118]
  PIN b[119]
    DIRECTION OUTPUT ;
    USE SIGNAL ;
    PORT
      LAYER M4 ;
        RECT  21.516 8.64 21.6 8.664 ;
    END
  END b[119]
  PIN b[11]
    DIRECTION OUTPUT ;
    USE SIGNAL ;
    PORT
      LAYER M4 ;
        RECT  21.516 2.304 21.6 2.328 ;
    END
  END b[11]
  PIN b[120]
    DIRECTION OUTPUT ;
    USE SIGNAL ;
    PORT
      LAYER M4 ;
        RECT  21.516 8.784 21.6 8.808 ;
    END
  END b[120]
  PIN b[121]
    DIRECTION OUTPUT ;
    USE SIGNAL ;
    PORT
      LAYER M4 ;
        RECT  21.516 8.928 21.6 8.952 ;
    END
  END b[121]
  PIN b[122]
    DIRECTION OUTPUT ;
    USE SIGNAL ;
    PORT
      LAYER M4 ;
        RECT  21.516 9.072 21.6 9.096 ;
    END
  END b[122]
  PIN b[123]
    DIRECTION OUTPUT ;
    USE SIGNAL ;
    PORT
      LAYER M4 ;
        RECT  21.516 9.216 21.6 9.24 ;
    END
  END b[123]
  PIN b[124]
    DIRECTION OUTPUT ;
    USE SIGNAL ;
    PORT
      LAYER M4 ;
        RECT  21.516 9.36 21.6 9.384 ;
    END
  END b[124]
  PIN b[125]
    DIRECTION OUTPUT ;
    USE SIGNAL ;
    PORT
      LAYER M4 ;
        RECT  21.516 9.504 21.6 9.528 ;
    END
  END b[125]
  PIN b[126]
    DIRECTION OUTPUT ;
    USE SIGNAL ;
    PORT
      LAYER M4 ;
        RECT  21.516 9.648 21.6 9.672 ;
    END
  END b[126]
  PIN b[127]
    DIRECTION OUTPUT ;
    USE SIGNAL ;
    PORT
      LAYER M4 ;
        RECT  21.516 9.792 21.6 9.816 ;
    END
  END b[127]
  PIN b[128]
    DIRECTION OUTPUT ;
    USE SIGNAL ;
    PORT
      LAYER M4 ;
        RECT  21.516 23.76 21.6 23.784 ;
    END
  END b[128]
  PIN b[129]
    DIRECTION OUTPUT ;
    USE SIGNAL ;
    PORT
      LAYER M4 ;
        RECT  21.516 23.904 21.6 23.928 ;
    END
  END b[129]
  PIN b[12]
    DIRECTION OUTPUT ;
    USE SIGNAL ;
    PORT
      LAYER M4 ;
        RECT  21.516 2.448 21.6 2.472 ;
    END
  END b[12]
  PIN b[130]
    DIRECTION OUTPUT ;
    USE SIGNAL ;
    PORT
      LAYER M4 ;
        RECT  21.516 24.048 21.6 24.072 ;
    END
  END b[130]
  PIN b[131]
    DIRECTION OUTPUT ;
    USE SIGNAL ;
    PORT
      LAYER M4 ;
        RECT  21.516 24.192 21.6 24.216 ;
    END
  END b[131]
  PIN b[132]
    DIRECTION OUTPUT ;
    USE SIGNAL ;
    PORT
      LAYER M4 ;
        RECT  21.516 24.336 21.6 24.36 ;
    END
  END b[132]
  PIN b[133]
    DIRECTION OUTPUT ;
    USE SIGNAL ;
    PORT
      LAYER M4 ;
        RECT  21.516 24.48 21.6 24.504 ;
    END
  END b[133]
  PIN b[134]
    DIRECTION OUTPUT ;
    USE SIGNAL ;
    PORT
      LAYER M4 ;
        RECT  21.516 24.624 21.6 24.648 ;
    END
  END b[134]
  PIN b[135]
    DIRECTION OUTPUT ;
    USE SIGNAL ;
    PORT
      LAYER M4 ;
        RECT  21.516 24.768 21.6 24.792 ;
    END
  END b[135]
  PIN b[136]
    DIRECTION OUTPUT ;
    USE SIGNAL ;
    PORT
      LAYER M4 ;
        RECT  21.516 24.912 21.6 24.936 ;
    END
  END b[136]
  PIN b[137]
    DIRECTION OUTPUT ;
    USE SIGNAL ;
    PORT
      LAYER M4 ;
        RECT  21.516 25.056 21.6 25.08 ;
    END
  END b[137]
  PIN b[138]
    DIRECTION OUTPUT ;
    USE SIGNAL ;
    PORT
      LAYER M4 ;
        RECT  21.516 25.2 21.6 25.224 ;
    END
  END b[138]
  PIN b[139]
    DIRECTION OUTPUT ;
    USE SIGNAL ;
    PORT
      LAYER M4 ;
        RECT  21.516 25.344 21.6 25.368 ;
    END
  END b[139]
  PIN b[13]
    DIRECTION OUTPUT ;
    USE SIGNAL ;
    PORT
      LAYER M4 ;
        RECT  21.516 2.592 21.6 2.616 ;
    END
  END b[13]
  PIN b[140]
    DIRECTION OUTPUT ;
    USE SIGNAL ;
    PORT
      LAYER M4 ;
        RECT  21.516 25.488 21.6 25.512 ;
    END
  END b[140]
  PIN b[141]
    DIRECTION OUTPUT ;
    USE SIGNAL ;
    PORT
      LAYER M4 ;
        RECT  21.516 25.632 21.6 25.656 ;
    END
  END b[141]
  PIN b[142]
    DIRECTION OUTPUT ;
    USE SIGNAL ;
    PORT
      LAYER M4 ;
        RECT  21.516 25.776 21.6 25.8 ;
    END
  END b[142]
  PIN b[143]
    DIRECTION OUTPUT ;
    USE SIGNAL ;
    PORT
      LAYER M4 ;
        RECT  21.516 25.92 21.6 25.944 ;
    END
  END b[143]
  PIN b[144]
    DIRECTION OUTPUT ;
    USE SIGNAL ;
    PORT
      LAYER M4 ;
        RECT  21.516 26.064 21.6 26.088 ;
    END
  END b[144]
  PIN b[145]
    DIRECTION OUTPUT ;
    USE SIGNAL ;
    PORT
      LAYER M4 ;
        RECT  21.516 26.208 21.6 26.232 ;
    END
  END b[145]
  PIN b[146]
    DIRECTION OUTPUT ;
    USE SIGNAL ;
    PORT
      LAYER M4 ;
        RECT  21.516 26.352 21.6 26.376 ;
    END
  END b[146]
  PIN b[147]
    DIRECTION OUTPUT ;
    USE SIGNAL ;
    PORT
      LAYER M4 ;
        RECT  21.516 26.496 21.6 26.52 ;
    END
  END b[147]
  PIN b[148]
    DIRECTION OUTPUT ;
    USE SIGNAL ;
    PORT
      LAYER M4 ;
        RECT  21.516 26.64 21.6 26.664 ;
    END
  END b[148]
  PIN b[149]
    DIRECTION OUTPUT ;
    USE SIGNAL ;
    PORT
      LAYER M4 ;
        RECT  21.516 26.784 21.6 26.808 ;
    END
  END b[149]
  PIN b[14]
    DIRECTION OUTPUT ;
    USE SIGNAL ;
    PORT
      LAYER M4 ;
        RECT  21.516 2.736 21.6 2.76 ;
    END
  END b[14]
  PIN b[150]
    DIRECTION OUTPUT ;
    USE SIGNAL ;
    PORT
      LAYER M4 ;
        RECT  21.516 26.928 21.6 26.952 ;
    END
  END b[150]
  PIN b[151]
    DIRECTION OUTPUT ;
    USE SIGNAL ;
    PORT
      LAYER M4 ;
        RECT  21.516 27.072 21.6 27.096 ;
    END
  END b[151]
  PIN b[152]
    DIRECTION OUTPUT ;
    USE SIGNAL ;
    PORT
      LAYER M4 ;
        RECT  21.516 27.216 21.6 27.24 ;
    END
  END b[152]
  PIN b[153]
    DIRECTION OUTPUT ;
    USE SIGNAL ;
    PORT
      LAYER M4 ;
        RECT  21.516 27.36 21.6 27.384 ;
    END
  END b[153]
  PIN b[154]
    DIRECTION OUTPUT ;
    USE SIGNAL ;
    PORT
      LAYER M4 ;
        RECT  21.516 27.504 21.6 27.528 ;
    END
  END b[154]
  PIN b[155]
    DIRECTION OUTPUT ;
    USE SIGNAL ;
    PORT
      LAYER M4 ;
        RECT  21.516 27.648 21.6 27.672 ;
    END
  END b[155]
  PIN b[156]
    DIRECTION OUTPUT ;
    USE SIGNAL ;
    PORT
      LAYER M4 ;
        RECT  21.516 27.792 21.6 27.816 ;
    END
  END b[156]
  PIN b[157]
    DIRECTION OUTPUT ;
    USE SIGNAL ;
    PORT
      LAYER M4 ;
        RECT  21.516 27.936 21.6 27.96 ;
    END
  END b[157]
  PIN b[158]
    DIRECTION OUTPUT ;
    USE SIGNAL ;
    PORT
      LAYER M4 ;
        RECT  21.516 28.08 21.6 28.104 ;
    END
  END b[158]
  PIN b[159]
    DIRECTION OUTPUT ;
    USE SIGNAL ;
    PORT
      LAYER M4 ;
        RECT  21.516 28.224 21.6 28.248 ;
    END
  END b[159]
  PIN b[15]
    DIRECTION OUTPUT ;
    USE SIGNAL ;
    PORT
      LAYER M4 ;
        RECT  21.516 2.88 21.6 2.904 ;
    END
  END b[15]
  PIN b[160]
    DIRECTION OUTPUT ;
    USE SIGNAL ;
    PORT
      LAYER M4 ;
        RECT  21.516 19.152 21.6 19.176 ;
    END
  END b[160]
  PIN b[161]
    DIRECTION OUTPUT ;
    USE SIGNAL ;
    PORT
      LAYER M4 ;
        RECT  21.516 19.296 21.6 19.32 ;
    END
  END b[161]
  PIN b[162]
    DIRECTION OUTPUT ;
    USE SIGNAL ;
    PORT
      LAYER M4 ;
        RECT  21.516 19.44 21.6 19.464 ;
    END
  END b[162]
  PIN b[163]
    DIRECTION OUTPUT ;
    USE SIGNAL ;
    PORT
      LAYER M4 ;
        RECT  21.516 19.584 21.6 19.608 ;
    END
  END b[163]
  PIN b[164]
    DIRECTION OUTPUT ;
    USE SIGNAL ;
    PORT
      LAYER M4 ;
        RECT  21.516 19.728 21.6 19.752 ;
    END
  END b[164]
  PIN b[165]
    DIRECTION OUTPUT ;
    USE SIGNAL ;
    PORT
      LAYER M4 ;
        RECT  21.516 19.872 21.6 19.896 ;
    END
  END b[165]
  PIN b[166]
    DIRECTION OUTPUT ;
    USE SIGNAL ;
    PORT
      LAYER M4 ;
        RECT  21.516 20.016 21.6 20.04 ;
    END
  END b[166]
  PIN b[167]
    DIRECTION OUTPUT ;
    USE SIGNAL ;
    PORT
      LAYER M4 ;
        RECT  21.516 20.16 21.6 20.184 ;
    END
  END b[167]
  PIN b[168]
    DIRECTION OUTPUT ;
    USE SIGNAL ;
    PORT
      LAYER M4 ;
        RECT  21.516 20.304 21.6 20.328 ;
    END
  END b[168]
  PIN b[169]
    DIRECTION OUTPUT ;
    USE SIGNAL ;
    PORT
      LAYER M4 ;
        RECT  21.516 20.448 21.6 20.472 ;
    END
  END b[169]
  PIN b[16]
    DIRECTION OUTPUT ;
    USE SIGNAL ;
    PORT
      LAYER M4 ;
        RECT  21.516 3.024 21.6 3.048 ;
    END
  END b[16]
  PIN b[170]
    DIRECTION OUTPUT ;
    USE SIGNAL ;
    PORT
      LAYER M4 ;
        RECT  21.516 20.592 21.6 20.616 ;
    END
  END b[170]
  PIN b[171]
    DIRECTION OUTPUT ;
    USE SIGNAL ;
    PORT
      LAYER M4 ;
        RECT  21.516 20.736 21.6 20.76 ;
    END
  END b[171]
  PIN b[172]
    DIRECTION OUTPUT ;
    USE SIGNAL ;
    PORT
      LAYER M4 ;
        RECT  21.516 20.88 21.6 20.904 ;
    END
  END b[172]
  PIN b[173]
    DIRECTION OUTPUT ;
    USE SIGNAL ;
    PORT
      LAYER M4 ;
        RECT  21.516 21.024 21.6 21.048 ;
    END
  END b[173]
  PIN b[174]
    DIRECTION OUTPUT ;
    USE SIGNAL ;
    PORT
      LAYER M4 ;
        RECT  21.516 21.168 21.6 21.192 ;
    END
  END b[174]
  PIN b[175]
    DIRECTION OUTPUT ;
    USE SIGNAL ;
    PORT
      LAYER M4 ;
        RECT  21.516 21.312 21.6 21.336 ;
    END
  END b[175]
  PIN b[176]
    DIRECTION OUTPUT ;
    USE SIGNAL ;
    PORT
      LAYER M4 ;
        RECT  21.516 21.456 21.6 21.48 ;
    END
  END b[176]
  PIN b[177]
    DIRECTION OUTPUT ;
    USE SIGNAL ;
    PORT
      LAYER M4 ;
        RECT  21.516 21.6 21.6 21.624 ;
    END
  END b[177]
  PIN b[178]
    DIRECTION OUTPUT ;
    USE SIGNAL ;
    PORT
      LAYER M4 ;
        RECT  21.516 21.744 21.6 21.768 ;
    END
  END b[178]
  PIN b[179]
    DIRECTION OUTPUT ;
    USE SIGNAL ;
    PORT
      LAYER M4 ;
        RECT  21.516 21.888 21.6 21.912 ;
    END
  END b[179]
  PIN b[17]
    DIRECTION OUTPUT ;
    USE SIGNAL ;
    PORT
      LAYER M4 ;
        RECT  21.516 3.168 21.6 3.192 ;
    END
  END b[17]
  PIN b[180]
    DIRECTION OUTPUT ;
    USE SIGNAL ;
    PORT
      LAYER M4 ;
        RECT  21.516 22.032 21.6 22.056 ;
    END
  END b[180]
  PIN b[181]
    DIRECTION OUTPUT ;
    USE SIGNAL ;
    PORT
      LAYER M4 ;
        RECT  21.516 22.176 21.6 22.2 ;
    END
  END b[181]
  PIN b[182]
    DIRECTION OUTPUT ;
    USE SIGNAL ;
    PORT
      LAYER M4 ;
        RECT  21.516 22.32 21.6 22.344 ;
    END
  END b[182]
  PIN b[183]
    DIRECTION OUTPUT ;
    USE SIGNAL ;
    PORT
      LAYER M4 ;
        RECT  21.516 22.464 21.6 22.488 ;
    END
  END b[183]
  PIN b[184]
    DIRECTION OUTPUT ;
    USE SIGNAL ;
    PORT
      LAYER M4 ;
        RECT  21.516 22.608 21.6 22.632 ;
    END
  END b[184]
  PIN b[185]
    DIRECTION OUTPUT ;
    USE SIGNAL ;
    PORT
      LAYER M4 ;
        RECT  21.516 22.752 21.6 22.776 ;
    END
  END b[185]
  PIN b[186]
    DIRECTION OUTPUT ;
    USE SIGNAL ;
    PORT
      LAYER M4 ;
        RECT  21.516 22.896 21.6 22.92 ;
    END
  END b[186]
  PIN b[187]
    DIRECTION OUTPUT ;
    USE SIGNAL ;
    PORT
      LAYER M4 ;
        RECT  21.516 23.04 21.6 23.064 ;
    END
  END b[187]
  PIN b[188]
    DIRECTION OUTPUT ;
    USE SIGNAL ;
    PORT
      LAYER M4 ;
        RECT  21.516 23.184 21.6 23.208 ;
    END
  END b[188]
  PIN b[189]
    DIRECTION OUTPUT ;
    USE SIGNAL ;
    PORT
      LAYER M4 ;
        RECT  21.516 23.328 21.6 23.352 ;
    END
  END b[189]
  PIN b[18]
    DIRECTION OUTPUT ;
    USE SIGNAL ;
    PORT
      LAYER M4 ;
        RECT  21.516 3.312 21.6 3.336 ;
    END
  END b[18]
  PIN b[190]
    DIRECTION OUTPUT ;
    USE SIGNAL ;
    PORT
      LAYER M4 ;
        RECT  21.516 23.472 21.6 23.496 ;
    END
  END b[190]
  PIN b[191]
    DIRECTION OUTPUT ;
    USE SIGNAL ;
    PORT
      LAYER M4 ;
        RECT  21.516 23.616 21.6 23.64 ;
    END
  END b[191]
  PIN b[192]
    DIRECTION OUTPUT ;
    USE SIGNAL ;
    PORT
      LAYER M4 ;
        RECT  21.516 29.52 21.6 29.544 ;
    END
  END b[192]
  PIN b[193]
    DIRECTION OUTPUT ;
    USE SIGNAL ;
    PORT
      LAYER M4 ;
        RECT  21.516 29.664 21.6 29.688 ;
    END
  END b[193]
  PIN b[194]
    DIRECTION OUTPUT ;
    USE SIGNAL ;
    PORT
      LAYER M4 ;
        RECT  21.516 29.808 21.6 29.832 ;
    END
  END b[194]
  PIN b[195]
    DIRECTION OUTPUT ;
    USE SIGNAL ;
    PORT
      LAYER M4 ;
        RECT  21.516 29.952 21.6 29.976 ;
    END
  END b[195]
  PIN b[196]
    DIRECTION OUTPUT ;
    USE SIGNAL ;
    PORT
      LAYER M4 ;
        RECT  21.516 30.096 21.6 30.12 ;
    END
  END b[196]
  PIN b[197]
    DIRECTION OUTPUT ;
    USE SIGNAL ;
    PORT
      LAYER M4 ;
        RECT  21.516 30.24 21.6 30.264 ;
    END
  END b[197]
  PIN b[198]
    DIRECTION OUTPUT ;
    USE SIGNAL ;
    PORT
      LAYER M4 ;
        RECT  21.516 30.384 21.6 30.408 ;
    END
  END b[198]
  PIN b[199]
    DIRECTION OUTPUT ;
    USE SIGNAL ;
    PORT
      LAYER M4 ;
        RECT  21.516 30.528 21.6 30.552 ;
    END
  END b[199]
  PIN b[19]
    DIRECTION OUTPUT ;
    USE SIGNAL ;
    PORT
      LAYER M4 ;
        RECT  21.516 3.456 21.6 3.48 ;
    END
  END b[19]
  PIN b[1]
    DIRECTION OUTPUT ;
    USE SIGNAL ;
    PORT
      LAYER M4 ;
        RECT  21.516 0.864 21.6 0.888 ;
    END
  END b[1]
  PIN b[200]
    DIRECTION OUTPUT ;
    USE SIGNAL ;
    PORT
      LAYER M4 ;
        RECT  21.516 30.672 21.6 30.696 ;
    END
  END b[200]
  PIN b[201]
    DIRECTION OUTPUT ;
    USE SIGNAL ;
    PORT
      LAYER M4 ;
        RECT  21.516 30.816 21.6 30.84 ;
    END
  END b[201]
  PIN b[202]
    DIRECTION OUTPUT ;
    USE SIGNAL ;
    PORT
      LAYER M4 ;
        RECT  21.516 30.96 21.6 30.984 ;
    END
  END b[202]
  PIN b[203]
    DIRECTION OUTPUT ;
    USE SIGNAL ;
    PORT
      LAYER M4 ;
        RECT  21.516 31.104 21.6 31.128 ;
    END
  END b[203]
  PIN b[204]
    DIRECTION OUTPUT ;
    USE SIGNAL ;
    PORT
      LAYER M4 ;
        RECT  21.516 31.248 21.6 31.272 ;
    END
  END b[204]
  PIN b[205]
    DIRECTION OUTPUT ;
    USE SIGNAL ;
    PORT
      LAYER M4 ;
        RECT  21.516 31.392 21.6 31.416 ;
    END
  END b[205]
  PIN b[206]
    DIRECTION OUTPUT ;
    USE SIGNAL ;
    PORT
      LAYER M4 ;
        RECT  21.516 31.536 21.6 31.56 ;
    END
  END b[206]
  PIN b[207]
    DIRECTION OUTPUT ;
    USE SIGNAL ;
    PORT
      LAYER M4 ;
        RECT  21.516 31.68 21.6 31.704 ;
    END
  END b[207]
  PIN b[208]
    DIRECTION OUTPUT ;
    USE SIGNAL ;
    PORT
      LAYER M4 ;
        RECT  21.516 31.824 21.6 31.848 ;
    END
  END b[208]
  PIN b[209]
    DIRECTION OUTPUT ;
    USE SIGNAL ;
    PORT
      LAYER M4 ;
        RECT  21.516 31.968 21.6 31.992 ;
    END
  END b[209]
  PIN b[20]
    DIRECTION OUTPUT ;
    USE SIGNAL ;
    PORT
      LAYER M4 ;
        RECT  21.516 3.6 21.6 3.624 ;
    END
  END b[20]
  PIN b[210]
    DIRECTION OUTPUT ;
    USE SIGNAL ;
    PORT
      LAYER M4 ;
        RECT  21.516 32.112 21.6 32.136 ;
    END
  END b[210]
  PIN b[211]
    DIRECTION OUTPUT ;
    USE SIGNAL ;
    PORT
      LAYER M4 ;
        RECT  21.516 32.256 21.6 32.28 ;
    END
  END b[211]
  PIN b[212]
    DIRECTION OUTPUT ;
    USE SIGNAL ;
    PORT
      LAYER M4 ;
        RECT  21.516 32.4 21.6 32.424 ;
    END
  END b[212]
  PIN b[213]
    DIRECTION OUTPUT ;
    USE SIGNAL ;
    PORT
      LAYER M4 ;
        RECT  21.516 32.544 21.6 32.568 ;
    END
  END b[213]
  PIN b[214]
    DIRECTION OUTPUT ;
    USE SIGNAL ;
    PORT
      LAYER M4 ;
        RECT  21.516 32.688 21.6 32.712 ;
    END
  END b[214]
  PIN b[215]
    DIRECTION OUTPUT ;
    USE SIGNAL ;
    PORT
      LAYER M4 ;
        RECT  21.516 32.832 21.6 32.856 ;
    END
  END b[215]
  PIN b[216]
    DIRECTION OUTPUT ;
    USE SIGNAL ;
    PORT
      LAYER M4 ;
        RECT  21.516 32.976 21.6 33 ;
    END
  END b[216]
  PIN b[217]
    DIRECTION OUTPUT ;
    USE SIGNAL ;
    PORT
      LAYER M4 ;
        RECT  21.516 33.12 21.6 33.144 ;
    END
  END b[217]
  PIN b[218]
    DIRECTION OUTPUT ;
    USE SIGNAL ;
    PORT
      LAYER M4 ;
        RECT  21.516 33.264 21.6 33.288 ;
    END
  END b[218]
  PIN b[219]
    DIRECTION OUTPUT ;
    USE SIGNAL ;
    PORT
      LAYER M4 ;
        RECT  21.516 33.408 21.6 33.432 ;
    END
  END b[219]
  PIN b[21]
    DIRECTION OUTPUT ;
    USE SIGNAL ;
    PORT
      LAYER M4 ;
        RECT  21.516 3.744 21.6 3.768 ;
    END
  END b[21]
  PIN b[220]
    DIRECTION OUTPUT ;
    USE SIGNAL ;
    PORT
      LAYER M4 ;
        RECT  21.516 33.552 21.6 33.576 ;
    END
  END b[220]
  PIN b[221]
    DIRECTION OUTPUT ;
    USE SIGNAL ;
    PORT
      LAYER M4 ;
        RECT  21.516 33.696 21.6 33.72 ;
    END
  END b[221]
  PIN b[222]
    DIRECTION OUTPUT ;
    USE SIGNAL ;
    PORT
      LAYER M4 ;
        RECT  21.516 33.84 21.6 33.864 ;
    END
  END b[222]
  PIN b[223]
    DIRECTION OUTPUT ;
    USE SIGNAL ;
    PORT
      LAYER M4 ;
        RECT  21.516 33.984 21.6 34.008 ;
    END
  END b[223]
  PIN b[224]
    DIRECTION OUTPUT ;
    USE SIGNAL ;
    PORT
      LAYER M4 ;
        RECT  21.516 38.736 21.6 38.76 ;
    END
  END b[224]
  PIN b[225]
    DIRECTION OUTPUT ;
    USE SIGNAL ;
    PORT
      LAYER M4 ;
        RECT  21.516 38.88 21.6 38.904 ;
    END
  END b[225]
  PIN b[226]
    DIRECTION OUTPUT ;
    USE SIGNAL ;
    PORT
      LAYER M4 ;
        RECT  21.516 39.024 21.6 39.048 ;
    END
  END b[226]
  PIN b[227]
    DIRECTION OUTPUT ;
    USE SIGNAL ;
    PORT
      LAYER M4 ;
        RECT  21.516 39.168 21.6 39.192 ;
    END
  END b[227]
  PIN b[228]
    DIRECTION OUTPUT ;
    USE SIGNAL ;
    PORT
      LAYER M4 ;
        RECT  21.516 39.312 21.6 39.336 ;
    END
  END b[228]
  PIN b[229]
    DIRECTION OUTPUT ;
    USE SIGNAL ;
    PORT
      LAYER M4 ;
        RECT  21.516 39.456 21.6 39.48 ;
    END
  END b[229]
  PIN b[22]
    DIRECTION OUTPUT ;
    USE SIGNAL ;
    PORT
      LAYER M4 ;
        RECT  21.516 3.888 21.6 3.912 ;
    END
  END b[22]
  PIN b[230]
    DIRECTION OUTPUT ;
    USE SIGNAL ;
    PORT
      LAYER M4 ;
        RECT  21.516 39.6 21.6 39.624 ;
    END
  END b[230]
  PIN b[231]
    DIRECTION OUTPUT ;
    USE SIGNAL ;
    PORT
      LAYER M4 ;
        RECT  21.516 39.744 21.6 39.768 ;
    END
  END b[231]
  PIN b[232]
    DIRECTION OUTPUT ;
    USE SIGNAL ;
    PORT
      LAYER M4 ;
        RECT  21.516 39.888 21.6 39.912 ;
    END
  END b[232]
  PIN b[233]
    DIRECTION OUTPUT ;
    USE SIGNAL ;
    PORT
      LAYER M4 ;
        RECT  21.516 40.032 21.6 40.056 ;
    END
  END b[233]
  PIN b[234]
    DIRECTION OUTPUT ;
    USE SIGNAL ;
    PORT
      LAYER M4 ;
        RECT  21.516 40.176 21.6 40.2 ;
    END
  END b[234]
  PIN b[235]
    DIRECTION OUTPUT ;
    USE SIGNAL ;
    PORT
      LAYER M4 ;
        RECT  21.516 40.32 21.6 40.344 ;
    END
  END b[235]
  PIN b[236]
    DIRECTION OUTPUT ;
    USE SIGNAL ;
    PORT
      LAYER M4 ;
        RECT  21.516 40.464 21.6 40.488 ;
    END
  END b[236]
  PIN b[237]
    DIRECTION OUTPUT ;
    USE SIGNAL ;
    PORT
      LAYER M4 ;
        RECT  21.516 40.608 21.6 40.632 ;
    END
  END b[237]
  PIN b[238]
    DIRECTION OUTPUT ;
    USE SIGNAL ;
    PORT
      LAYER M4 ;
        RECT  21.516 40.752 21.6 40.776 ;
    END
  END b[238]
  PIN b[239]
    DIRECTION OUTPUT ;
    USE SIGNAL ;
    PORT
      LAYER M4 ;
        RECT  21.516 40.896 21.6 40.92 ;
    END
  END b[239]
  PIN b[23]
    DIRECTION OUTPUT ;
    USE SIGNAL ;
    PORT
      LAYER M4 ;
        RECT  21.516 4.032 21.6 4.056 ;
    END
  END b[23]
  PIN b[240]
    DIRECTION OUTPUT ;
    USE SIGNAL ;
    PORT
      LAYER M4 ;
        RECT  21.516 41.04 21.6 41.064 ;
    END
  END b[240]
  PIN b[241]
    DIRECTION OUTPUT ;
    USE SIGNAL ;
    PORT
      LAYER M4 ;
        RECT  21.516 41.184 21.6 41.208 ;
    END
  END b[241]
  PIN b[242]
    DIRECTION OUTPUT ;
    USE SIGNAL ;
    PORT
      LAYER M4 ;
        RECT  21.516 41.328 21.6 41.352 ;
    END
  END b[242]
  PIN b[243]
    DIRECTION OUTPUT ;
    USE SIGNAL ;
    PORT
      LAYER M4 ;
        RECT  21.516 41.472 21.6 41.496 ;
    END
  END b[243]
  PIN b[244]
    DIRECTION OUTPUT ;
    USE SIGNAL ;
    PORT
      LAYER M4 ;
        RECT  21.516 41.616 21.6 41.64 ;
    END
  END b[244]
  PIN b[245]
    DIRECTION OUTPUT ;
    USE SIGNAL ;
    PORT
      LAYER M4 ;
        RECT  21.516 41.76 21.6 41.784 ;
    END
  END b[245]
  PIN b[246]
    DIRECTION OUTPUT ;
    USE SIGNAL ;
    PORT
      LAYER M4 ;
        RECT  21.516 41.904 21.6 41.928 ;
    END
  END b[246]
  PIN b[247]
    DIRECTION OUTPUT ;
    USE SIGNAL ;
    PORT
      LAYER M4 ;
        RECT  21.516 42.048 21.6 42.072 ;
    END
  END b[247]
  PIN b[248]
    DIRECTION OUTPUT ;
    USE SIGNAL ;
    PORT
      LAYER M4 ;
        RECT  21.516 42.192 21.6 42.216 ;
    END
  END b[248]
  PIN b[249]
    DIRECTION OUTPUT ;
    USE SIGNAL ;
    PORT
      LAYER M4 ;
        RECT  21.516 42.336 21.6 42.36 ;
    END
  END b[249]
  PIN b[24]
    DIRECTION OUTPUT ;
    USE SIGNAL ;
    PORT
      LAYER M4 ;
        RECT  21.516 4.176 21.6 4.2 ;
    END
  END b[24]
  PIN b[250]
    DIRECTION OUTPUT ;
    USE SIGNAL ;
    PORT
      LAYER M4 ;
        RECT  21.516 42.48 21.6 42.504 ;
    END
  END b[250]
  PIN b[251]
    DIRECTION OUTPUT ;
    USE SIGNAL ;
    PORT
      LAYER M4 ;
        RECT  21.516 42.624 21.6 42.648 ;
    END
  END b[251]
  PIN b[252]
    DIRECTION OUTPUT ;
    USE SIGNAL ;
    PORT
      LAYER M4 ;
        RECT  21.516 42.768 21.6 42.792 ;
    END
  END b[252]
  PIN b[253]
    DIRECTION OUTPUT ;
    USE SIGNAL ;
    PORT
      LAYER M4 ;
        RECT  21.516 42.912 21.6 42.936 ;
    END
  END b[253]
  PIN b[254]
    DIRECTION OUTPUT ;
    USE SIGNAL ;
    PORT
      LAYER M4 ;
        RECT  21.516 43.056 21.6 43.08 ;
    END
  END b[254]
  PIN b[255]
    DIRECTION OUTPUT ;
    USE SIGNAL ;
    PORT
      LAYER M4 ;
        RECT  21.516 43.2 21.6 43.224 ;
    END
  END b[255]
  PIN b[256]
    DIRECTION OUTPUT ;
    USE SIGNAL ;
    PORT
      LAYER M4 ;
        RECT  21.516 34.128 21.6 34.152 ;
    END
  END b[256]
  PIN b[257]
    DIRECTION OUTPUT ;
    USE SIGNAL ;
    PORT
      LAYER M4 ;
        RECT  21.516 34.272 21.6 34.296 ;
    END
  END b[257]
  PIN b[258]
    DIRECTION OUTPUT ;
    USE SIGNAL ;
    PORT
      LAYER M4 ;
        RECT  21.516 34.416 21.6 34.44 ;
    END
  END b[258]
  PIN b[259]
    DIRECTION OUTPUT ;
    USE SIGNAL ;
    PORT
      LAYER M4 ;
        RECT  21.516 34.56 21.6 34.584 ;
    END
  END b[259]
  PIN b[25]
    DIRECTION OUTPUT ;
    USE SIGNAL ;
    PORT
      LAYER M4 ;
        RECT  21.516 4.32 21.6 4.344 ;
    END
  END b[25]
  PIN b[260]
    DIRECTION OUTPUT ;
    USE SIGNAL ;
    PORT
      LAYER M4 ;
        RECT  21.516 34.704 21.6 34.728 ;
    END
  END b[260]
  PIN b[261]
    DIRECTION OUTPUT ;
    USE SIGNAL ;
    PORT
      LAYER M4 ;
        RECT  21.516 34.848 21.6 34.872 ;
    END
  END b[261]
  PIN b[262]
    DIRECTION OUTPUT ;
    USE SIGNAL ;
    PORT
      LAYER M4 ;
        RECT  21.516 34.992 21.6 35.016 ;
    END
  END b[262]
  PIN b[263]
    DIRECTION OUTPUT ;
    USE SIGNAL ;
    PORT
      LAYER M4 ;
        RECT  21.516 35.136 21.6 35.16 ;
    END
  END b[263]
  PIN b[264]
    DIRECTION OUTPUT ;
    USE SIGNAL ;
    PORT
      LAYER M4 ;
        RECT  21.516 35.28 21.6 35.304 ;
    END
  END b[264]
  PIN b[265]
    DIRECTION OUTPUT ;
    USE SIGNAL ;
    PORT
      LAYER M4 ;
        RECT  21.516 35.424 21.6 35.448 ;
    END
  END b[265]
  PIN b[266]
    DIRECTION OUTPUT ;
    USE SIGNAL ;
    PORT
      LAYER M4 ;
        RECT  21.516 35.568 21.6 35.592 ;
    END
  END b[266]
  PIN b[267]
    DIRECTION OUTPUT ;
    USE SIGNAL ;
    PORT
      LAYER M4 ;
        RECT  21.516 35.712 21.6 35.736 ;
    END
  END b[267]
  PIN b[268]
    DIRECTION OUTPUT ;
    USE SIGNAL ;
    PORT
      LAYER M4 ;
        RECT  21.516 35.856 21.6 35.88 ;
    END
  END b[268]
  PIN b[269]
    DIRECTION OUTPUT ;
    USE SIGNAL ;
    PORT
      LAYER M4 ;
        RECT  21.516 36 21.6 36.024 ;
    END
  END b[269]
  PIN b[26]
    DIRECTION OUTPUT ;
    USE SIGNAL ;
    PORT
      LAYER M4 ;
        RECT  21.516 4.464 21.6 4.488 ;
    END
  END b[26]
  PIN b[270]
    DIRECTION OUTPUT ;
    USE SIGNAL ;
    PORT
      LAYER M4 ;
        RECT  21.516 36.144 21.6 36.168 ;
    END
  END b[270]
  PIN b[271]
    DIRECTION OUTPUT ;
    USE SIGNAL ;
    PORT
      LAYER M4 ;
        RECT  21.516 36.288 21.6 36.312 ;
    END
  END b[271]
  PIN b[272]
    DIRECTION OUTPUT ;
    USE SIGNAL ;
    PORT
      LAYER M4 ;
        RECT  21.516 36.432 21.6 36.456 ;
    END
  END b[272]
  PIN b[273]
    DIRECTION OUTPUT ;
    USE SIGNAL ;
    PORT
      LAYER M4 ;
        RECT  21.516 36.576 21.6 36.6 ;
    END
  END b[273]
  PIN b[274]
    DIRECTION OUTPUT ;
    USE SIGNAL ;
    PORT
      LAYER M4 ;
        RECT  21.516 36.72 21.6 36.744 ;
    END
  END b[274]
  PIN b[275]
    DIRECTION OUTPUT ;
    USE SIGNAL ;
    PORT
      LAYER M4 ;
        RECT  21.516 36.864 21.6 36.888 ;
    END
  END b[275]
  PIN b[276]
    DIRECTION OUTPUT ;
    USE SIGNAL ;
    PORT
      LAYER M4 ;
        RECT  21.516 37.008 21.6 37.032 ;
    END
  END b[276]
  PIN b[277]
    DIRECTION OUTPUT ;
    USE SIGNAL ;
    PORT
      LAYER M4 ;
        RECT  21.516 37.152 21.6 37.176 ;
    END
  END b[277]
  PIN b[278]
    DIRECTION OUTPUT ;
    USE SIGNAL ;
    PORT
      LAYER M4 ;
        RECT  21.516 37.296 21.6 37.32 ;
    END
  END b[278]
  PIN b[279]
    DIRECTION OUTPUT ;
    USE SIGNAL ;
    PORT
      LAYER M4 ;
        RECT  21.516 37.44 21.6 37.464 ;
    END
  END b[279]
  PIN b[27]
    DIRECTION OUTPUT ;
    USE SIGNAL ;
    PORT
      LAYER M4 ;
        RECT  21.516 4.608 21.6 4.632 ;
    END
  END b[27]
  PIN b[280]
    DIRECTION OUTPUT ;
    USE SIGNAL ;
    PORT
      LAYER M4 ;
        RECT  21.516 37.584 21.6 37.608 ;
    END
  END b[280]
  PIN b[281]
    DIRECTION OUTPUT ;
    USE SIGNAL ;
    PORT
      LAYER M4 ;
        RECT  21.516 37.728 21.6 37.752 ;
    END
  END b[281]
  PIN b[282]
    DIRECTION OUTPUT ;
    USE SIGNAL ;
    PORT
      LAYER M4 ;
        RECT  21.516 37.872 21.6 37.896 ;
    END
  END b[282]
  PIN b[283]
    DIRECTION OUTPUT ;
    USE SIGNAL ;
    PORT
      LAYER M4 ;
        RECT  21.516 38.016 21.6 38.04 ;
    END
  END b[283]
  PIN b[284]
    DIRECTION OUTPUT ;
    USE SIGNAL ;
    PORT
      LAYER M4 ;
        RECT  21.516 38.16 21.6 38.184 ;
    END
  END b[284]
  PIN b[285]
    DIRECTION OUTPUT ;
    USE SIGNAL ;
    PORT
      LAYER M4 ;
        RECT  21.516 38.304 21.6 38.328 ;
    END
  END b[285]
  PIN b[286]
    DIRECTION OUTPUT ;
    USE SIGNAL ;
    PORT
      LAYER M4 ;
        RECT  21.516 38.448 21.6 38.472 ;
    END
  END b[286]
  PIN b[287]
    DIRECTION OUTPUT ;
    USE SIGNAL ;
    PORT
      LAYER M4 ;
        RECT  21.516 38.592 21.6 38.616 ;
    END
  END b[287]
  PIN b[288]
    DIRECTION OUTPUT ;
    USE SIGNAL ;
    PORT
      LAYER M4 ;
        RECT  21.516 28.368 21.6 28.392 ;
    END
  END b[288]
  PIN b[289]
    DIRECTION OUTPUT ;
    USE SIGNAL ;
    PORT
      LAYER M4 ;
        RECT  21.516 28.512 21.6 28.536 ;
    END
  END b[289]
  PIN b[28]
    DIRECTION OUTPUT ;
    USE SIGNAL ;
    PORT
      LAYER M4 ;
        RECT  21.516 4.752 21.6 4.776 ;
    END
  END b[28]
  PIN b[290]
    DIRECTION OUTPUT ;
    USE SIGNAL ;
    PORT
      LAYER M4 ;
        RECT  21.516 28.656 21.6 28.68 ;
    END
  END b[290]
  PIN b[291]
    DIRECTION OUTPUT ;
    USE SIGNAL ;
    PORT
      LAYER M4 ;
        RECT  21.516 28.8 21.6 28.824 ;
    END
  END b[291]
  PIN b[292]
    DIRECTION OUTPUT ;
    USE SIGNAL ;
    PORT
      LAYER M4 ;
        RECT  21.516 28.944 21.6 28.968 ;
    END
  END b[292]
  PIN b[293]
    DIRECTION OUTPUT ;
    USE SIGNAL ;
    PORT
      LAYER M4 ;
        RECT  21.516 29.088 21.6 29.112 ;
    END
  END b[293]
  PIN b[294]
    DIRECTION OUTPUT ;
    USE SIGNAL ;
    PORT
      LAYER M4 ;
        RECT  21.516 29.232 21.6 29.256 ;
    END
  END b[294]
  PIN b[295]
    DIRECTION OUTPUT ;
    USE SIGNAL ;
    PORT
      LAYER M4 ;
        RECT  21.516 29.376 21.6 29.4 ;
    END
  END b[295]
  PIN b[29]
    DIRECTION OUTPUT ;
    USE SIGNAL ;
    PORT
      LAYER M4 ;
        RECT  21.516 4.896 21.6 4.92 ;
    END
  END b[29]
  PIN b[2]
    DIRECTION OUTPUT ;
    USE SIGNAL ;
    PORT
      LAYER M4 ;
        RECT  21.516 1.008 21.6 1.032 ;
    END
  END b[2]
  PIN b[30]
    DIRECTION OUTPUT ;
    USE SIGNAL ;
    PORT
      LAYER M4 ;
        RECT  21.516 5.04 21.6 5.064 ;
    END
  END b[30]
  PIN b[31]
    DIRECTION OUTPUT ;
    USE SIGNAL ;
    PORT
      LAYER M4 ;
        RECT  21.516 5.184 21.6 5.208 ;
    END
  END b[31]
  PIN b[32]
    DIRECTION OUTPUT ;
    USE SIGNAL ;
    PORT
      LAYER M4 ;
        RECT  21.516 14.544 21.6 14.568 ;
    END
  END b[32]
  PIN b[33]
    DIRECTION OUTPUT ;
    USE SIGNAL ;
    PORT
      LAYER M4 ;
        RECT  21.516 14.688 21.6 14.712 ;
    END
  END b[33]
  PIN b[34]
    DIRECTION OUTPUT ;
    USE SIGNAL ;
    PORT
      LAYER M4 ;
        RECT  21.516 14.832 21.6 14.856 ;
    END
  END b[34]
  PIN b[35]
    DIRECTION OUTPUT ;
    USE SIGNAL ;
    PORT
      LAYER M4 ;
        RECT  21.516 14.976 21.6 15 ;
    END
  END b[35]
  PIN b[36]
    DIRECTION OUTPUT ;
    USE SIGNAL ;
    PORT
      LAYER M4 ;
        RECT  21.516 15.12 21.6 15.144 ;
    END
  END b[36]
  PIN b[37]
    DIRECTION OUTPUT ;
    USE SIGNAL ;
    PORT
      LAYER M4 ;
        RECT  21.516 15.264 21.6 15.288 ;
    END
  END b[37]
  PIN b[38]
    DIRECTION OUTPUT ;
    USE SIGNAL ;
    PORT
      LAYER M4 ;
        RECT  21.516 15.408 21.6 15.432 ;
    END
  END b[38]
  PIN b[39]
    DIRECTION OUTPUT ;
    USE SIGNAL ;
    PORT
      LAYER M4 ;
        RECT  21.516 15.552 21.6 15.576 ;
    END
  END b[39]
  PIN b[3]
    DIRECTION OUTPUT ;
    USE SIGNAL ;
    PORT
      LAYER M4 ;
        RECT  21.516 1.152 21.6 1.176 ;
    END
  END b[3]
  PIN b[40]
    DIRECTION OUTPUT ;
    USE SIGNAL ;
    PORT
      LAYER M4 ;
        RECT  21.516 15.696 21.6 15.72 ;
    END
  END b[40]
  PIN b[41]
    DIRECTION OUTPUT ;
    USE SIGNAL ;
    PORT
      LAYER M4 ;
        RECT  21.516 15.84 21.6 15.864 ;
    END
  END b[41]
  PIN b[42]
    DIRECTION OUTPUT ;
    USE SIGNAL ;
    PORT
      LAYER M4 ;
        RECT  21.516 15.984 21.6 16.008 ;
    END
  END b[42]
  PIN b[43]
    DIRECTION OUTPUT ;
    USE SIGNAL ;
    PORT
      LAYER M4 ;
        RECT  21.516 16.128 21.6 16.152 ;
    END
  END b[43]
  PIN b[44]
    DIRECTION OUTPUT ;
    USE SIGNAL ;
    PORT
      LAYER M4 ;
        RECT  21.516 16.272 21.6 16.296 ;
    END
  END b[44]
  PIN b[45]
    DIRECTION OUTPUT ;
    USE SIGNAL ;
    PORT
      LAYER M4 ;
        RECT  21.516 16.416 21.6 16.44 ;
    END
  END b[45]
  PIN b[46]
    DIRECTION OUTPUT ;
    USE SIGNAL ;
    PORT
      LAYER M4 ;
        RECT  21.516 16.56 21.6 16.584 ;
    END
  END b[46]
  PIN b[47]
    DIRECTION OUTPUT ;
    USE SIGNAL ;
    PORT
      LAYER M4 ;
        RECT  21.516 16.704 21.6 16.728 ;
    END
  END b[47]
  PIN b[48]
    DIRECTION OUTPUT ;
    USE SIGNAL ;
    PORT
      LAYER M4 ;
        RECT  21.516 16.848 21.6 16.872 ;
    END
  END b[48]
  PIN b[49]
    DIRECTION OUTPUT ;
    USE SIGNAL ;
    PORT
      LAYER M4 ;
        RECT  21.516 16.992 21.6 17.016 ;
    END
  END b[49]
  PIN b[4]
    DIRECTION OUTPUT ;
    USE SIGNAL ;
    PORT
      LAYER M4 ;
        RECT  21.516 1.296 21.6 1.32 ;
    END
  END b[4]
  PIN b[50]
    DIRECTION OUTPUT ;
    USE SIGNAL ;
    PORT
      LAYER M4 ;
        RECT  21.516 17.136 21.6 17.16 ;
    END
  END b[50]
  PIN b[51]
    DIRECTION OUTPUT ;
    USE SIGNAL ;
    PORT
      LAYER M4 ;
        RECT  21.516 17.28 21.6 17.304 ;
    END
  END b[51]
  PIN b[52]
    DIRECTION OUTPUT ;
    USE SIGNAL ;
    PORT
      LAYER M4 ;
        RECT  21.516 17.424 21.6 17.448 ;
    END
  END b[52]
  PIN b[53]
    DIRECTION OUTPUT ;
    USE SIGNAL ;
    PORT
      LAYER M4 ;
        RECT  21.516 17.568 21.6 17.592 ;
    END
  END b[53]
  PIN b[54]
    DIRECTION OUTPUT ;
    USE SIGNAL ;
    PORT
      LAYER M4 ;
        RECT  21.516 17.712 21.6 17.736 ;
    END
  END b[54]
  PIN b[55]
    DIRECTION OUTPUT ;
    USE SIGNAL ;
    PORT
      LAYER M4 ;
        RECT  21.516 17.856 21.6 17.88 ;
    END
  END b[55]
  PIN b[56]
    DIRECTION OUTPUT ;
    USE SIGNAL ;
    PORT
      LAYER M4 ;
        RECT  21.516 18 21.6 18.024 ;
    END
  END b[56]
  PIN b[57]
    DIRECTION OUTPUT ;
    USE SIGNAL ;
    PORT
      LAYER M4 ;
        RECT  21.516 18.144 21.6 18.168 ;
    END
  END b[57]
  PIN b[58]
    DIRECTION OUTPUT ;
    USE SIGNAL ;
    PORT
      LAYER M4 ;
        RECT  21.516 18.288 21.6 18.312 ;
    END
  END b[58]
  PIN b[59]
    DIRECTION OUTPUT ;
    USE SIGNAL ;
    PORT
      LAYER M4 ;
        RECT  21.516 18.432 21.6 18.456 ;
    END
  END b[59]
  PIN b[5]
    DIRECTION OUTPUT ;
    USE SIGNAL ;
    PORT
      LAYER M4 ;
        RECT  21.516 1.44 21.6 1.464 ;
    END
  END b[5]
  PIN b[60]
    DIRECTION OUTPUT ;
    USE SIGNAL ;
    PORT
      LAYER M4 ;
        RECT  21.516 18.576 21.6 18.6 ;
    END
  END b[60]
  PIN b[61]
    DIRECTION OUTPUT ;
    USE SIGNAL ;
    PORT
      LAYER M4 ;
        RECT  21.516 18.72 21.6 18.744 ;
    END
  END b[61]
  PIN b[62]
    DIRECTION OUTPUT ;
    USE SIGNAL ;
    PORT
      LAYER M4 ;
        RECT  21.516 18.864 21.6 18.888 ;
    END
  END b[62]
  PIN b[63]
    DIRECTION OUTPUT ;
    USE SIGNAL ;
    PORT
      LAYER M4 ;
        RECT  21.516 19.008 21.6 19.032 ;
    END
  END b[63]
  PIN b[64]
    DIRECTION OUTPUT ;
    USE SIGNAL ;
    PORT
      LAYER M4 ;
        RECT  21.516 9.936 21.6 9.96 ;
    END
  END b[64]
  PIN b[65]
    DIRECTION OUTPUT ;
    USE SIGNAL ;
    PORT
      LAYER M4 ;
        RECT  21.516 10.08 21.6 10.104 ;
    END
  END b[65]
  PIN b[66]
    DIRECTION OUTPUT ;
    USE SIGNAL ;
    PORT
      LAYER M4 ;
        RECT  21.516 10.224 21.6 10.248 ;
    END
  END b[66]
  PIN b[67]
    DIRECTION OUTPUT ;
    USE SIGNAL ;
    PORT
      LAYER M4 ;
        RECT  21.516 10.368 21.6 10.392 ;
    END
  END b[67]
  PIN b[68]
    DIRECTION OUTPUT ;
    USE SIGNAL ;
    PORT
      LAYER M4 ;
        RECT  21.516 10.512 21.6 10.536 ;
    END
  END b[68]
  PIN b[69]
    DIRECTION OUTPUT ;
    USE SIGNAL ;
    PORT
      LAYER M4 ;
        RECT  21.516 10.656 21.6 10.68 ;
    END
  END b[69]
  PIN b[6]
    DIRECTION OUTPUT ;
    USE SIGNAL ;
    PORT
      LAYER M4 ;
        RECT  21.516 1.584 21.6 1.608 ;
    END
  END b[6]
  PIN b[70]
    DIRECTION OUTPUT ;
    USE SIGNAL ;
    PORT
      LAYER M4 ;
        RECT  21.516 10.8 21.6 10.824 ;
    END
  END b[70]
  PIN b[71]
    DIRECTION OUTPUT ;
    USE SIGNAL ;
    PORT
      LAYER M4 ;
        RECT  21.516 10.944 21.6 10.968 ;
    END
  END b[71]
  PIN b[72]
    DIRECTION OUTPUT ;
    USE SIGNAL ;
    PORT
      LAYER M4 ;
        RECT  21.516 11.088 21.6 11.112 ;
    END
  END b[72]
  PIN b[73]
    DIRECTION OUTPUT ;
    USE SIGNAL ;
    PORT
      LAYER M4 ;
        RECT  21.516 11.232 21.6 11.256 ;
    END
  END b[73]
  PIN b[74]
    DIRECTION OUTPUT ;
    USE SIGNAL ;
    PORT
      LAYER M4 ;
        RECT  21.516 11.376 21.6 11.4 ;
    END
  END b[74]
  PIN b[75]
    DIRECTION OUTPUT ;
    USE SIGNAL ;
    PORT
      LAYER M4 ;
        RECT  21.516 11.52 21.6 11.544 ;
    END
  END b[75]
  PIN b[76]
    DIRECTION OUTPUT ;
    USE SIGNAL ;
    PORT
      LAYER M4 ;
        RECT  21.516 11.664 21.6 11.688 ;
    END
  END b[76]
  PIN b[77]
    DIRECTION OUTPUT ;
    USE SIGNAL ;
    PORT
      LAYER M4 ;
        RECT  21.516 11.808 21.6 11.832 ;
    END
  END b[77]
  PIN b[78]
    DIRECTION OUTPUT ;
    USE SIGNAL ;
    PORT
      LAYER M4 ;
        RECT  21.516 11.952 21.6 11.976 ;
    END
  END b[78]
  PIN b[79]
    DIRECTION OUTPUT ;
    USE SIGNAL ;
    PORT
      LAYER M4 ;
        RECT  21.516 12.096 21.6 12.12 ;
    END
  END b[79]
  PIN b[7]
    DIRECTION OUTPUT ;
    USE SIGNAL ;
    PORT
      LAYER M4 ;
        RECT  21.516 1.728 21.6 1.752 ;
    END
  END b[7]
  PIN b[80]
    DIRECTION OUTPUT ;
    USE SIGNAL ;
    PORT
      LAYER M4 ;
        RECT  21.516 12.24 21.6 12.264 ;
    END
  END b[80]
  PIN b[81]
    DIRECTION OUTPUT ;
    USE SIGNAL ;
    PORT
      LAYER M4 ;
        RECT  21.516 12.384 21.6 12.408 ;
    END
  END b[81]
  PIN b[82]
    DIRECTION OUTPUT ;
    USE SIGNAL ;
    PORT
      LAYER M4 ;
        RECT  21.516 12.528 21.6 12.552 ;
    END
  END b[82]
  PIN b[83]
    DIRECTION OUTPUT ;
    USE SIGNAL ;
    PORT
      LAYER M4 ;
        RECT  21.516 12.672 21.6 12.696 ;
    END
  END b[83]
  PIN b[84]
    DIRECTION OUTPUT ;
    USE SIGNAL ;
    PORT
      LAYER M4 ;
        RECT  21.516 12.816 21.6 12.84 ;
    END
  END b[84]
  PIN b[85]
    DIRECTION OUTPUT ;
    USE SIGNAL ;
    PORT
      LAYER M4 ;
        RECT  21.516 12.96 21.6 12.984 ;
    END
  END b[85]
  PIN b[86]
    DIRECTION OUTPUT ;
    USE SIGNAL ;
    PORT
      LAYER M4 ;
        RECT  21.516 13.104 21.6 13.128 ;
    END
  END b[86]
  PIN b[87]
    DIRECTION OUTPUT ;
    USE SIGNAL ;
    PORT
      LAYER M4 ;
        RECT  21.516 13.248 21.6 13.272 ;
    END
  END b[87]
  PIN b[88]
    DIRECTION OUTPUT ;
    USE SIGNAL ;
    PORT
      LAYER M4 ;
        RECT  21.516 13.392 21.6 13.416 ;
    END
  END b[88]
  PIN b[89]
    DIRECTION OUTPUT ;
    USE SIGNAL ;
    PORT
      LAYER M4 ;
        RECT  21.516 13.536 21.6 13.56 ;
    END
  END b[89]
  PIN b[8]
    DIRECTION OUTPUT ;
    USE SIGNAL ;
    PORT
      LAYER M4 ;
        RECT  21.516 1.872 21.6 1.896 ;
    END
  END b[8]
  PIN b[90]
    DIRECTION OUTPUT ;
    USE SIGNAL ;
    PORT
      LAYER M4 ;
        RECT  21.516 13.68 21.6 13.704 ;
    END
  END b[90]
  PIN b[91]
    DIRECTION OUTPUT ;
    USE SIGNAL ;
    PORT
      LAYER M4 ;
        RECT  21.516 13.824 21.6 13.848 ;
    END
  END b[91]
  PIN b[92]
    DIRECTION OUTPUT ;
    USE SIGNAL ;
    PORT
      LAYER M4 ;
        RECT  21.516 13.968 21.6 13.992 ;
    END
  END b[92]
  PIN b[93]
    DIRECTION OUTPUT ;
    USE SIGNAL ;
    PORT
      LAYER M4 ;
        RECT  21.516 14.112 21.6 14.136 ;
    END
  END b[93]
  PIN b[94]
    DIRECTION OUTPUT ;
    USE SIGNAL ;
    PORT
      LAYER M4 ;
        RECT  21.516 14.256 21.6 14.28 ;
    END
  END b[94]
  PIN b[95]
    DIRECTION OUTPUT ;
    USE SIGNAL ;
    PORT
      LAYER M4 ;
        RECT  21.516 14.4 21.6 14.424 ;
    END
  END b[95]
  PIN b[96]
    DIRECTION OUTPUT ;
    USE SIGNAL ;
    PORT
      LAYER M4 ;
        RECT  21.516 5.328 21.6 5.352 ;
    END
  END b[96]
  PIN b[97]
    DIRECTION OUTPUT ;
    USE SIGNAL ;
    PORT
      LAYER M4 ;
        RECT  21.516 5.472 21.6 5.496 ;
    END
  END b[97]
  PIN b[98]
    DIRECTION OUTPUT ;
    USE SIGNAL ;
    PORT
      LAYER M4 ;
        RECT  21.516 5.616 21.6 5.64 ;
    END
  END b[98]
  PIN b[99]
    DIRECTION OUTPUT ;
    USE SIGNAL ;
    PORT
      LAYER M4 ;
        RECT  21.516 5.76 21.6 5.784 ;
    END
  END b[99]
  PIN b[9]
    DIRECTION OUTPUT ;
    USE SIGNAL ;
    PORT
      LAYER M4 ;
        RECT  21.516 2.016 21.6 2.04 ;
    END
  END b[9]
  PIN ck_o
    DIRECTION OUTPUT ;
    USE SIGNAL ;
    PORT
      LAYER M3 ;
        RECT  15.876 47.483 15.894 47.52 ;
    END
  END ck_o
  PIN ckf
    DIRECTION INPUT ;
    USE SIGNAL ;
    PORT
      LAYER M3 ;
        RECT  15.228 0 15.246 0.037 ;
    END
  END ckf
  PIN ea
    DIRECTION INPUT ;
    USE SIGNAL ;
    PORT
      LAYER M3 ;
        RECT  15.336 0 15.354 0.037 ;
    END
  END ea
  PIN eb
    DIRECTION OUTPUT ;
    USE SIGNAL ;
    PORT
      LAYER M3 ;
        RECT  15.984 47.483 16.002 47.52 ;
    END
  END eb
  PIN VDD
    DIRECTION INOUT ;
    USE POWER ;
    PORT
      LAYER M5 ;
        RECT  18.792 2.151 18.912 45.369 ;
        RECT  16.092 2.151 16.212 45.369 ;
        RECT  13.392 2.151 13.512 45.369 ;
        RECT  10.692 2.151 10.812 45.369 ;
        RECT  7.992 2.151 8.112 45.369 ;
        RECT  5.292 2.151 5.412 45.369 ;
        RECT  2.592 2.151 2.712 45.369 ;
    END
  END VDD
  PIN VSS
    DIRECTION INOUT ;
    USE GROUND ;
    PORT
      LAYER M5 ;
        RECT  18.6 2.137 18.72 45.383 ;
        RECT  15.9 2.137 16.02 45.383 ;
        RECT  13.2 2.137 13.32 45.383 ;
        RECT  10.5 2.137 10.62 45.383 ;
        RECT  7.8 2.137 7.92 45.383 ;
        RECT  5.1 2.137 5.22 45.383 ;
        RECT  2.4 2.137 2.52 45.383 ;
    END
  END VSS
  OBS
    LAYER RVTN ;
     RECT  2.16 2.16 19.44 2.295 ;
     RECT  2.16 2.565 19.44 2.835 ;
     RECT  2.16 3.105 19.44 3.375 ;
     RECT  2.16 3.645 19.44 3.915 ;
     RECT  2.16 4.185 19.44 4.455 ;
     RECT  2.16 4.725 19.44 4.995 ;
     RECT  2.16 5.265 19.44 5.535 ;
     RECT  2.16 5.805 19.44 6.075 ;
     RECT  2.16 6.345 19.44 6.615 ;
     RECT  2.16 6.885 19.44 7.155 ;
     RECT  2.16 7.425 19.44 7.695 ;
     RECT  2.16 7.965 19.44 8.235 ;
     RECT  2.16 8.505 19.44 8.775 ;
     RECT  2.16 9.045 19.44 9.315 ;
     RECT  2.16 9.585 19.44 9.855 ;
     RECT  2.16 10.125 19.44 10.395 ;
     RECT  2.16 10.665 19.44 10.935 ;
     RECT  2.16 11.205 19.44 11.475 ;
     RECT  2.16 11.745 19.44 12.015 ;
     RECT  2.16 12.285 19.44 12.555 ;
     RECT  2.16 12.825 19.44 13.095 ;
     RECT  2.16 13.365 19.44 13.635 ;
     RECT  2.16 13.905 19.44 14.175 ;
     RECT  2.16 14.445 19.44 14.715 ;
     RECT  2.16 14.985 19.44 15.255 ;
     RECT  2.16 15.525 19.44 15.795 ;
     RECT  2.16 16.065 19.44 16.335 ;
     RECT  2.16 16.605 19.44 16.875 ;
     RECT  2.16 17.145 19.44 17.415 ;
     RECT  2.16 17.685 19.44 17.955 ;
     RECT  2.16 18.225 19.44 18.495 ;
     RECT  2.16 18.765 19.44 19.035 ;
     RECT  2.16 19.305 19.44 19.575 ;
     RECT  2.16 19.845 19.44 20.115 ;
     RECT  2.16 20.385 19.44 20.655 ;
     RECT  2.16 20.925 19.44 21.195 ;
     RECT  2.16 21.465 19.44 21.735 ;
     RECT  2.16 22.005 19.44 22.275 ;
     RECT  2.16 22.545 19.44 22.815 ;
     RECT  2.16 23.085 19.44 23.355 ;
     RECT  2.16 23.625 19.44 23.895 ;
     RECT  2.16 24.165 19.44 24.435 ;
     RECT  2.16 24.705 19.44 24.975 ;
     RECT  2.16 25.245 19.44 25.515 ;
     RECT  2.16 25.785 19.44 26.055 ;
     RECT  2.16 26.325 19.44 26.595 ;
     RECT  2.16 26.865 19.44 27.135 ;
     RECT  2.16 27.405 19.44 27.675 ;
     RECT  2.16 27.945 19.44 28.215 ;
     RECT  2.16 28.485 19.44 28.755 ;
     RECT  2.16 29.025 19.44 29.295 ;
     RECT  2.16 29.565 19.44 29.835 ;
     RECT  2.16 30.105 19.44 30.375 ;
     RECT  2.16 30.645 19.44 30.915 ;
     RECT  2.16 31.185 19.44 31.455 ;
     RECT  2.16 31.725 19.44 31.995 ;
     RECT  2.16 32.265 19.44 32.535 ;
     RECT  2.16 32.805 19.44 33.075 ;
     RECT  2.16 33.345 19.44 33.615 ;
     RECT  2.16 33.885 19.44 34.155 ;
     RECT  2.16 34.425 19.44 34.695 ;
     RECT  2.16 34.965 19.44 35.235 ;
     RECT  2.16 35.505 19.44 35.775 ;
     RECT  2.16 36.045 19.44 36.315 ;
     RECT  2.16 36.585 19.44 36.855 ;
     RECT  2.16 37.125 19.44 37.395 ;
     RECT  2.16 37.665 19.44 37.935 ;
     RECT  2.16 38.205 19.44 38.475 ;
     RECT  2.16 38.745 19.44 39.015 ;
     RECT  2.16 39.285 19.44 39.555 ;
     RECT  2.16 39.825 19.44 40.095 ;
     RECT  2.16 40.365 19.44 40.635 ;
     RECT  2.16 40.905 19.44 41.175 ;
     RECT  2.16 41.445 19.44 41.715 ;
     RECT  2.16 41.985 19.44 42.255 ;
     RECT  2.16 42.525 19.44 42.795 ;
     RECT  2.16 43.065 19.44 43.335 ;
     RECT  2.16 43.605 19.44 43.875 ;
     RECT  2.16 44.145 19.44 44.415 ;
     RECT  2.16 44.685 19.44 44.955 ;
     RECT  2.16 45.225 19.44 45.36 ;
    LAYER RVTP ;
     RECT  2.16 2.295 19.44 2.565 ;
     RECT  2.16 2.835 19.44 3.105 ;
     RECT  2.16 3.375 19.44 3.645 ;
     RECT  2.16 3.915 19.44 4.185 ;
     RECT  2.16 4.455 19.44 4.725 ;
     RECT  2.16 4.995 19.44 5.265 ;
     RECT  2.16 5.535 19.44 5.805 ;
     RECT  2.16 6.075 19.44 6.345 ;
     RECT  2.16 6.615 19.44 6.885 ;
     RECT  2.16 7.155 19.44 7.425 ;
     RECT  2.16 7.695 19.44 7.965 ;
     RECT  2.16 8.235 19.44 8.505 ;
     RECT  2.16 8.775 19.44 9.045 ;
     RECT  2.16 9.315 19.44 9.585 ;
     RECT  2.16 9.855 19.44 10.125 ;
     RECT  2.16 10.395 19.44 10.665 ;
     RECT  2.16 10.935 19.44 11.205 ;
     RECT  2.16 11.475 19.44 11.745 ;
     RECT  2.16 12.015 19.44 12.285 ;
     RECT  2.16 12.555 19.44 12.825 ;
     RECT  2.16 13.095 19.44 13.365 ;
     RECT  2.16 13.635 19.44 13.905 ;
     RECT  2.16 14.175 19.44 14.445 ;
     RECT  2.16 14.715 19.44 14.985 ;
     RECT  2.16 15.255 19.44 15.525 ;
     RECT  2.16 15.795 19.44 16.065 ;
     RECT  2.16 16.335 19.44 16.605 ;
     RECT  2.16 16.875 19.44 17.145 ;
     RECT  2.16 17.415 19.44 17.685 ;
     RECT  2.16 17.955 19.44 18.225 ;
     RECT  2.16 18.495 19.44 18.765 ;
     RECT  2.16 19.035 19.44 19.305 ;
     RECT  2.16 19.575 19.44 19.845 ;
     RECT  2.16 20.115 19.44 20.385 ;
     RECT  2.16 20.655 19.44 20.925 ;
     RECT  2.16 21.195 19.44 21.465 ;
     RECT  2.16 21.735 19.44 22.005 ;
     RECT  2.16 22.275 19.44 22.545 ;
     RECT  2.16 22.815 19.44 23.085 ;
     RECT  2.16 23.355 19.44 23.625 ;
     RECT  2.16 23.895 19.44 24.165 ;
     RECT  2.16 24.435 19.44 24.705 ;
     RECT  2.16 24.975 19.44 25.245 ;
     RECT  2.16 25.515 19.44 25.785 ;
     RECT  2.16 26.055 19.44 26.325 ;
     RECT  2.16 26.595 19.44 26.865 ;
     RECT  2.16 27.135 19.44 27.405 ;
     RECT  2.16 27.675 19.44 27.945 ;
     RECT  2.16 28.215 19.44 28.485 ;
     RECT  2.16 28.755 19.44 29.025 ;
     RECT  2.16 29.295 19.44 29.565 ;
     RECT  2.16 29.835 19.44 30.105 ;
     RECT  2.16 30.375 19.44 30.645 ;
     RECT  2.16 30.915 19.44 31.185 ;
     RECT  2.16 31.455 19.44 31.725 ;
     RECT  2.16 31.995 19.44 32.265 ;
     RECT  2.16 32.535 19.44 32.805 ;
     RECT  2.16 33.075 19.44 33.345 ;
     RECT  2.16 33.615 19.44 33.885 ;
     RECT  2.16 34.155 19.44 34.425 ;
     RECT  2.16 34.695 19.44 34.965 ;
     RECT  2.16 35.235 19.44 35.505 ;
     RECT  2.16 35.775 19.44 36.045 ;
     RECT  2.16 36.315 19.44 36.585 ;
     RECT  2.16 36.855 19.44 37.125 ;
     RECT  2.16 37.395 19.44 37.665 ;
     RECT  2.16 37.935 19.44 38.205 ;
     RECT  2.16 38.475 19.44 38.745 ;
     RECT  2.16 39.015 19.44 39.285 ;
     RECT  2.16 39.555 19.44 39.825 ;
     RECT  2.16 40.095 19.44 40.365 ;
     RECT  2.16 40.635 19.44 40.905 ;
     RECT  2.16 41.175 19.44 41.445 ;
     RECT  2.16 41.715 19.44 41.985 ;
     RECT  2.16 42.255 19.44 42.525 ;
     RECT  2.16 42.795 19.44 43.065 ;
     RECT  2.16 43.335 19.44 43.605 ;
     RECT  2.16 43.875 19.44 44.145 ;
     RECT  2.16 44.415 19.44 44.685 ;
     RECT  2.16 44.955 19.44 45.225 ;
    LAYER M1 ;
     RECT  2.16 2.151 19.44 45.369 ;
    LAYER M2 ;
     RECT  0.103 35.748 0.139 35.766 ;
     RECT  0.103 20.736 0.175 20.754 ;
     RECT  0.103 29.376 0.175 29.394 ;
     RECT  0.103 38.016 0.175 38.034 ;
     RECT  0.175 20.628 0.203 20.754 ;
     RECT  0.175 29.268 0.203 29.394 ;
     RECT  0.203 20.628 0.275 20.646 ;
     RECT  0.203 29.268 0.275 29.286 ;
     RECT  0.175 37.908 0.463 38.034 ;
     RECT  0.103 40.14 0.463 40.158 ;
     RECT  0.463 43.272 0.499 43.29 ;
     RECT  0.463 27.882 0.535 27.9 ;
     RECT  0.463 37.908 0.535 38.16 ;
     RECT  0.463 39.834 0.535 40.158 ;
     RECT  0.499 42.732 0.535 43.29 ;
     RECT  0.499 44.424 0.535 44.442 ;
     RECT  0.103 18.846 2.16 18.864 ;
     RECT  0.535 22.626 2.16 22.644 ;
     RECT  0.535 23.832 2.16 23.85 ;
     RECT  0.535 27.342 2.16 29.052 ;
     RECT  0.535 31.77 2.16 31.788 ;
     RECT  0.535 33.552 2.16 34.11 ;
     RECT  0.139 35.748 2.16 36.144 ;
     RECT  0.535 37.602 2.16 38.196 ;
     RECT  0.535 39.294 2.16 40.158 ;
     RECT  0.535 42.606 2.16 44.442 ;
     RECT  2.16 2.151 2.839 45.369 ;
     RECT  2.839 2.151 6.143 45.414 ;
     RECT  6.143 2.151 15.979 45.369 ;
     RECT  15.979 2.151 16.151 45.594 ;
     RECT  16.151 2.151 19.44 45.369 ;
     RECT  19.44 39.096 19.463 39.114 ;
     RECT  19.44 7.128 19.679 7.146 ;
     RECT  19.44 44.316 19.679 44.604 ;
     RECT  19.44 5.976 19.931 5.994 ;
     RECT  19.44 10.026 19.931 35.064 ;
     RECT  19.931 10.026 19.967 13.464 ;
     RECT  19.931 14.616 19.967 35.064 ;
     RECT  19.967 14.616 20.003 33.066 ;
     RECT  19.679 44.316 20.219 44.334 ;
     RECT  20.003 14.616 20.291 32.598 ;
     RECT  19.967 10.026 20.507 12.474 ;
     RECT  19.967 13.266 20.507 13.464 ;
     RECT  20.291 14.616 20.507 16.254 ;
     RECT  20.291 17.082 20.507 32.598 ;
     RECT  20.507 14.796 20.543 15.984 ;
     RECT  20.507 17.118 20.543 19.098 ;
     RECT  20.507 19.854 20.543 29.394 ;
     RECT  20.507 30.654 20.543 32.598 ;
     RECT  19.967 34.092 20.543 35.064 ;
     RECT  20.543 31.77 20.579 32.49 ;
     RECT  20.543 34.434 20.579 34.452 ;
     RECT  20.579 31.77 20.615 31.914 ;
     RECT  20.543 20.394 21.119 29.394 ;
     RECT  20.543 17.118 21.155 19.062 ;
     RECT  21.119 21.168 21.191 29.394 ;
     RECT  20.615 31.896 21.227 31.914 ;
     RECT  21.191 22.986 21.263 29.394 ;
     RECT  21.263 28.836 21.299 29.394 ;
     RECT  21.299 28.836 21.335 29.214 ;
     RECT  21.263 22.986 21.371 27.864 ;
     RECT  20.507 10.566 21.415 10.584 ;
     RECT  20.507 11.448 21.415 12.114 ;
     RECT  21.415 10.566 21.443 12.114 ;
     RECT  21.155 17.586 21.443 17.874 ;
     RECT  21.155 19.044 21.443 19.062 ;
     RECT  21.191 21.168 21.443 21.834 ;
     RECT  21.343 5.202 21.451 5.22 ;
     RECT  21.451 5.076 21.479 5.22 ;
     RECT  21.343 8.361 21.479 8.379 ;
     RECT  21.443 10.566 21.479 10.809 ;
     RECT  21.443 11.646 21.479 11.664 ;
     RECT  20.507 13.446 21.479 13.464 ;
     RECT  20.543 15.066 21.479 15.984 ;
     RECT  21.443 17.586 21.479 17.604 ;
     RECT  21.119 20.394 21.479 20.412 ;
     RECT  21.443 21.51 21.479 21.834 ;
     RECT  21.371 22.986 21.479 25.974 ;
     RECT  21.371 27.036 21.479 27.864 ;
     RECT  21.335 29.196 21.515 29.214 ;
     RECT  20.543 30.654 21.515 30.672 ;
     RECT  21.479 5.076 21.551 5.094 ;
     RECT  21.479 25.956 21.551 25.974 ;
     RECT  21.487 1.881 21.587 1.899 ;
     RECT  21.479 10.791 21.587 10.809 ;
     RECT  21.479 15.066 21.587 15.084 ;
     RECT  21.487 39.294 21.587 39.312 ;
    LAYER M3 ;
     RECT  15.228 0.012 15.354 0.043 ;
     RECT  15.012 0.043 15.354 0.173 ;
     RECT  15.336 0.173 15.354 1.003 ;
     RECT  13.932 0.859 13.95 1.579 ;
     RECT  14.76 1.003 15.354 1.579 ;
     RECT  21.168 0.715 21.186 1.867 ;
     RECT  21.168 1.867 21.51 1.876 ;
     RECT  16.92 2.011 16.938 2.059 ;
     RECT  11.124 1.723 11.142 2.143 ;
     RECT  12.528 1.435 12.546 2.143 ;
     RECT  13.932 1.579 15.354 2.143 ;
     RECT  10.515 2.143 11.142 2.299 ;
     RECT  2.415 2.143 2.505 2.413 ;
     RECT  5.115 2.143 5.205 2.413 ;
     RECT  7.815 2.143 7.905 2.413 ;
     RECT  12.528 2.143 16.005 2.413 ;
     RECT  16.812 2.059 16.938 2.413 ;
     RECT  18.615 2.143 18.705 2.413 ;
     RECT  20.34 1.291 20.358 2.731 ;
     RECT  10.515 2.299 11.178 2.875 ;
     RECT  10.515 2.875 11.754 3.643 ;
     RECT  12.528 2.413 16.938 3.643 ;
     RECT  18.615 2.413 18.897 3.835 ;
     RECT  18.036 3.835 18.897 4.171 ;
     RECT  19.656 2.731 20.358 4.171 ;
     RECT  4.032 4.171 4.05 4.253 ;
     RECT  5.115 2.413 5.397 4.261 ;
     RECT  2.415 2.413 2.697 4.315 ;
     RECT  10.515 3.643 16.938 4.411 ;
     RECT  18.036 4.171 20.358 4.411 ;
     RECT  6.444 4.261 6.714 4.423 ;
     RECT  4.104 4.261 5.397 4.495 ;
     RECT  4.104 4.495 5.598 4.657 ;
     RECT  4.104 4.657 5.67 4.693 ;
     RECT  6.444 4.423 6.858 4.693 ;
     RECT  2.304 4.315 2.697 4.747 ;
     RECT  2.304 4.747 2.79 4.765 ;
     RECT  7.815 2.413 8.097 4.801 ;
     RECT  4.104 4.693 6.858 4.919 ;
     RECT  4.14 4.919 6.858 5.071 ;
     RECT  7.704 4.801 8.097 5.071 ;
     RECT  10.515 4.411 20.358 5.323 ;
     RECT  2.304 4.765 3.186 5.611 ;
     RECT  4.14 5.071 8.097 5.611 ;
     RECT  2.304 5.611 3.294 5.881 ;
     RECT  4.14 5.611 8.73 5.881 ;
     RECT  9.612 1.147 9.63 5.881 ;
     RECT  2.304 5.881 9.63 6.547 ;
     RECT  2.304 6.547 9.774 6.575 ;
     RECT  4.284 6.575 9.774 6.655 ;
     RECT  10.515 5.323 20.394 6.655 ;
     RECT  2.304 6.575 2.754 6.667 ;
     RECT  2.16 6.667 2.754 6.797 ;
     RECT  3.528 6.575 3.546 7.339 ;
     RECT  4.284 6.655 20.394 7.339 ;
     RECT  2.304 6.797 2.754 7.387 ;
     RECT  3.528 7.339 20.394 7.387 ;
     RECT  2.304 7.387 20.394 7.529 ;
     RECT  0.18 8.059 0.198 8.189 ;
     RECT  2.412 7.529 20.394 8.195 ;
     RECT  2.412 8.195 2.79 8.635 ;
     RECT  2.304 8.635 2.79 8.941 ;
     RECT  3.528 8.195 20.394 8.941 ;
     RECT  2.304 8.941 20.394 10.021 ;
     RECT  21.168 1.876 21.582 10.021 ;
     RECT  2.304 10.021 21.582 10.814 ;
     RECT  0.144 10.699 0.162 10.829 ;
     RECT  2.304 10.814 21.546 11.309 ;
     RECT  2.304 11.309 20.394 12.091 ;
     RECT  21.132 11.309 21.546 12.091 ;
     RECT  0.144 13.243 0.162 13.373 ;
     RECT  0.144 14.251 0.162 14.957 ;
     RECT  2.304 12.091 21.546 15.061 ;
     RECT  2.304 15.061 21.582 16.169 ;
     RECT  2.34 16.169 21.582 16.987 ;
     RECT  2.304 16.987 21.582 17.105 ;
     RECT  0.144 16.699 0.162 17.309 ;
     RECT  2.415 17.105 21.582 17.851 ;
     RECT  0.108 18.841 0.126 18.893 ;
     RECT  2.304 17.851 21.582 20.353 ;
     RECT  2.268 20.353 21.582 20.477 ;
     RECT  0.18 20.587 0.198 20.623 ;
     RECT  0.18 20.623 0.27 20.669 ;
     RECT  0.18 20.669 0.198 20.731 ;
     RECT  0.108 20.731 0.198 20.759 ;
     RECT  0.108 20.759 0.126 20.768 ;
     RECT  0.144 21.787 0.162 21.917 ;
     RECT  0.54 22.621 0.558 22.925 ;
     RECT  0.54 23.827 0.558 24.077 ;
     RECT  2.304 20.477 21.582 24.395 ;
     RECT  0.144 24.667 0.162 24.797 ;
     RECT  2.415 24.395 21.582 25.177 ;
     RECT  2.304 25.177 21.582 25.229 ;
     RECT  0.144 25.819 0.162 25.949 ;
     RECT  2.415 25.229 21.582 25.963 ;
     RECT  0.216 25.963 0.234 26.093 ;
     RECT  2.304 25.963 21.582 26.797 ;
     RECT  2.268 26.797 21.582 26.957 ;
     RECT  0.54 27.337 0.558 27.877 ;
     RECT  2.304 26.957 21.582 28.445 ;
     RECT  0.468 27.877 0.558 28.651 ;
     RECT  0.144 28.651 0.558 29.117 ;
     RECT  0.144 29.117 0.27 29.309 ;
     RECT  0.144 29.309 0.198 29.371 ;
     RECT  0.108 29.371 0.198 29.399 ;
     RECT  0.108 29.399 0.126 29.408 ;
     RECT  2.415 28.445 21.582 29.659 ;
     RECT  0.18 31.531 0.198 31.757 ;
     RECT  0.54 31.765 0.558 31.997 ;
     RECT  0.144 32.587 0.162 33.389 ;
     RECT  1.26 33.403 1.278 33.451 ;
     RECT  1.152 33.451 1.278 33.547 ;
     RECT  0.18 33.547 1.278 33.581 ;
     RECT  2.304 29.659 21.582 33.611 ;
     RECT  0.18 33.581 0.558 34.301 ;
     RECT  0.18 34.301 0.234 34.459 ;
     RECT  2.415 33.611 21.582 34.603 ;
     RECT  0.144 34.459 0.234 34.733 ;
     RECT  1.152 34.459 1.17 34.733 ;
     RECT  2.304 34.603 21.582 34.925 ;
     RECT  0.144 34.733 0.162 35.261 ;
     RECT  2.412 34.925 21.582 35.309 ;
     RECT  1.152 35.563 1.17 35.741 ;
     RECT  0.108 35.707 0.126 35.771 ;
     RECT  0.144 36.121 0.162 36.173 ;
     RECT  2.415 35.309 21.582 36.173 ;
     RECT  2.415 36.173 20.358 36.427 ;
     RECT  2.304 36.427 20.358 36.779 ;
     RECT  1.152 36.715 1.17 36.845 ;
     RECT  21.132 36.173 21.582 36.893 ;
     RECT  2.304 36.779 18.897 37.193 ;
     RECT  21.42 36.893 21.582 37.627 ;
     RECT  2.415 37.193 18.897 37.705 ;
     RECT  19.656 36.779 20.358 37.705 ;
     RECT  21.348 37.627 21.582 37.757 ;
     RECT  0.54 37.597 0.558 37.867 ;
     RECT  2.415 37.705 20.358 37.975 ;
     RECT  0.18 37.867 0.558 38.011 ;
     RECT  0.108 38.011 0.558 38.048 ;
     RECT  2.304 37.975 20.358 38.141 ;
     RECT  0.468 38.048 0.558 38.333 ;
     RECT  3.636 38.141 20.358 38.333 ;
     RECT  0.468 38.333 0.486 38.477 ;
     RECT  21.456 37.757 21.582 38.587 ;
     RECT  3.636 38.333 18.897 38.765 ;
     RECT  21.42 38.587 21.582 38.909 ;
     RECT  3.636 38.765 5.778 39.055 ;
     RECT  6.516 38.765 18.897 39.091 ;
     RECT  19.656 38.333 20.358 39.091 ;
     RECT  2.304 38.141 2.79 39.181 ;
     RECT  3.528 39.055 5.778 39.181 ;
     RECT  0.144 39.163 0.162 39.289 ;
     RECT  0.144 39.289 0.558 39.293 ;
     RECT  2.304 39.181 5.778 39.317 ;
     RECT  21.456 38.909 21.582 39.317 ;
     RECT  2.304 39.317 2.697 39.341 ;
     RECT  21.456 39.317 21.51 39.341 ;
     RECT  6.516 39.091 20.358 39.485 ;
     RECT  3.636 39.317 5.778 39.739 ;
     RECT  6.516 39.485 20.286 39.739 ;
     RECT  3.636 39.739 20.286 39.893 ;
     RECT  0.468 39.293 0.558 39.917 ;
     RECT  0.468 39.917 0.486 40.061 ;
     RECT  0.108 40.135 0.162 40.205 ;
     RECT  2.415 39.341 2.697 40.267 ;
     RECT  3.636 39.893 7.074 40.289 ;
     RECT  2.415 40.267 2.79 40.441 ;
     RECT  3.636 40.289 5.85 40.441 ;
     RECT  2.415 40.441 5.85 40.459 ;
     RECT  0.144 40.205 0.162 40.877 ;
     RECT  7.815 39.893 20.286 41.069 ;
     RECT  6.66 40.289 6.786 41.083 ;
     RECT  2.304 40.459 5.85 41.143 ;
     RECT  6.66 41.083 6.966 41.143 ;
     RECT  7.815 41.069 20.214 41.171 ;
     RECT  2.304 41.143 6.966 41.341 ;
     RECT  7.815 41.171 11.682 41.341 ;
     RECT  12.924 41.171 20.214 41.501 ;
     RECT  2.304 41.341 11.682 41.513 ;
     RECT  21.456 39.341 21.474 41.611 ;
     RECT  12.924 41.501 14.85 41.741 ;
     RECT  6.552 41.513 11.682 41.819 ;
     RECT  6.552 41.819 11.61 41.909 ;
     RECT  21.42 41.611 21.474 42.077 ;
     RECT  6.66 41.909 11.61 42.179 ;
     RECT  2.304 41.513 5.67 42.365 ;
     RECT  0.54 42.601 0.558 42.727 ;
     RECT  2.415 42.365 5.67 42.755 ;
     RECT  21.456 42.077 21.474 42.797 ;
     RECT  4.068 42.755 5.67 42.871 ;
     RECT  15.876 41.501 20.214 42.941 ;
     RECT  4.068 42.871 5.922 42.989 ;
     RECT  0.504 42.727 0.558 43.099 ;
     RECT  6.84 42.179 11.61 43.141 ;
     RECT  6.264 43.141 11.61 43.169 ;
     RECT  21.42 43.099 21.438 43.229 ;
     RECT  12.924 41.741 14.814 43.231 ;
     RECT  15.876 42.941 18.897 43.231 ;
     RECT  4.068 42.989 5.526 43.259 ;
     RECT  12.924 43.231 18.897 43.339 ;
     RECT  12.816 43.339 18.897 43.529 ;
     RECT  2.415 42.755 3.15 43.627 ;
     RECT  4.176 43.259 5.526 43.771 ;
     RECT  6.264 43.169 9.162 43.771 ;
     RECT  9.936 43.169 11.61 43.799 ;
     RECT  12.924 43.529 18.897 43.799 ;
     RECT  0.144 43.099 0.558 43.901 ;
     RECT  12.924 43.799 16.758 43.943 ;
     RECT  2.304 43.627 3.15 43.951 ;
     RECT  14.796 43.943 16.758 44.069 ;
     RECT  10.515 43.799 11.61 44.221 ;
     RECT  0.504 43.901 0.558 44.251 ;
     RECT  19.656 42.941 20.214 44.339 ;
     RECT  0.504 44.251 0.594 44.429 ;
     RECT  2.304 43.951 3.366 44.443 ;
     RECT  4.176 43.771 9.162 44.443 ;
     RECT  0.504 44.429 0.558 44.525 ;
     RECT  10.515 44.221 12.006 44.609 ;
     RECT  12.924 43.943 13.95 44.609 ;
     RECT  19.656 44.339 19.674 44.609 ;
     RECT  15.48 44.069 16.758 44.617 ;
     RECT  17.496 43.799 18.897 44.617 ;
     RECT  0.504 44.525 0.522 44.669 ;
     RECT  15.48 44.617 18.897 44.717 ;
     RECT  2.304 44.443 9.162 44.789 ;
     RECT  2.304 44.789 8.097 44.879 ;
     RECT  9.072 44.789 9.162 44.879 ;
     RECT  15.48 44.717 16.722 44.879 ;
     RECT  17.964 44.717 18.897 44.879 ;
     RECT  11.592 44.609 12.006 44.951 ;
     RECT  15.804 44.879 16.722 45.005 ;
     RECT  4.212 44.879 8.097 45.023 ;
     RECT  13.215 44.609 13.95 45.059 ;
     RECT  4.248 45.023 8.097 45.107 ;
     RECT  13.215 45.059 13.497 45.107 ;
     RECT  18.615 44.879 18.897 45.107 ;
     RECT  2.304 44.879 3.474 45.149 ;
     RECT  4.248 45.107 7.974 45.149 ;
     RECT  11.988 44.951 12.006 45.149 ;
     RECT  15.915 45.005 16.722 45.149 ;
     RECT  5.004 45.149 7.905 45.185 ;
     RECT  2.304 45.149 2.934 45.293 ;
     RECT  4.248 45.149 4.266 45.293 ;
     RECT  7.38 45.185 7.905 45.329 ;
     RECT  10.515 44.609 10.818 45.329 ;
     RECT  7.815 45.329 7.905 45.377 ;
     RECT  10.515 45.329 10.605 45.377 ;
     RECT  13.215 45.107 13.305 45.377 ;
     RECT  15.915 45.149 16.146 45.377 ;
     RECT  18.615 45.107 18.705 45.377 ;
     RECT  0.144 45.259 0.162 45.389 ;
     RECT  2.304 45.293 2.862 45.419 ;
     RECT  5.004 45.185 6.534 45.419 ;
     RECT  5.076 45.419 6.534 45.533 ;
     RECT  15.984 45.377 16.146 45.599 ;
     RECT  2.304 45.419 2.826 45.821 ;
     RECT  2.304 45.821 2.79 45.965 ;
     RECT  5.076 45.533 5.094 46.109 ;
     RECT  2.304 45.965 2.574 46.253 ;
     RECT  2.304 46.253 2.322 46.397 ;
     RECT  5.868 45.533 6.534 46.541 ;
     RECT  6.516 46.541 6.534 46.685 ;
     RECT  15.984 45.599 16.002 46.747 ;
     RECT  15.876 46.747 16.002 47.501 ;
    LAYER M4 ;
     RECT  0.06 4.176 2.408 46.68 ;
     RECT  2.408 2.148 2.512 46.68 ;
     RECT  2.512 2.418 2.704 46.68 ;
     RECT  2.704 4.176 4.025 46.68 ;
     RECT  4.025 4.176 4.061 27.672 ;
     RECT  4.025 28.656 5.105 46.68 ;
     RECT  4.061 4.464 5.108 27.672 ;
     RECT  5.105 28.656 5.108 45.528 ;
     RECT  5.108 2.148 5.212 45.528 ;
     RECT  5.212 2.418 5.404 45.528 ;
     RECT  5.404 6.336 5.501 6.936 ;
     RECT  5.404 22.464 5.501 42.552 ;
     RECT  5.404 16.8 5.537 21.432 ;
     RECT  5.404 8.16 5.555 10.104 ;
     RECT  5.501 22.464 5.555 40.056 ;
     RECT  5.404 11.424 5.573 13.368 ;
     RECT  5.404 45.504 5.573 45.528 ;
     RECT  5.404 4.512 5.609 5.208 ;
     RECT  5.501 41.088 5.609 42.552 ;
     RECT  5.404 14.4 5.651 15.048 ;
     RECT  5.609 4.704 5.681 5.208 ;
     RECT  5.555 8.16 5.681 9.864 ;
     RECT  5.501 6.912 5.717 6.936 ;
     RECT  5.651 14.4 5.717 15 ;
     RECT  5.537 17.28 5.717 21.432 ;
     RECT  5.555 22.464 5.717 40.008 ;
     RECT  5.609 41.088 5.747 42.216 ;
     RECT  5.573 11.424 5.891 13.32 ;
     RECT  5.105 46.512 5.897 46.68 ;
     RECT  5.891 13.296 5.932 13.32 ;
     RECT  5.717 27.312 5.969 40.008 ;
     RECT  5.969 32.4 6.083 40.008 ;
     RECT  5.969 27.312 6.179 30.84 ;
     RECT  6.083 32.4 6.185 39.768 ;
     RECT  6.179 27.312 6.257 28.824 ;
     RECT  6.257 27.312 6.473 27.864 ;
     RECT  5.897 46.656 6.545 46.68 ;
     RECT  5.681 8.16 6.653 9.192 ;
     RECT  5.717 14.4 6.685 14.424 ;
     RECT  6.653 8.208 6.797 9.192 ;
     RECT  6.473 27.312 6.797 27.672 ;
     RECT  5.717 23.04 6.829 25.752 ;
     RECT  6.797 27.312 6.829 27.336 ;
     RECT  6.185 32.4 6.833 39.624 ;
     RECT  6.829 23.04 6.901 27.336 ;
     RECT  5.717 18.48 7.1 21.432 ;
     RECT  6.901 22.608 7.1 27.336 ;
     RECT  5.404 44.4 7.189 44.424 ;
     RECT  6.179 30.336 7.532 30.84 ;
     RECT  7.532 30.24 7.573 30.84 ;
     RECT  7.117 5.76 7.808 5.784 ;
     RECT  6.797 8.208 7.808 9.096 ;
     RECT  6.613 10.176 7.808 10.2 ;
     RECT  5.891 11.424 7.808 11.976 ;
     RECT  6.685 14.4 7.808 15.384 ;
     RECT  7.1 18.48 7.808 27.336 ;
     RECT  7.573 29.616 7.808 30.84 ;
     RECT  6.833 32.4 7.808 32.424 ;
     RECT  6.833 34.608 7.808 39.624 ;
     RECT  5.747 41.088 7.808 41.64 ;
     RECT  6.829 42.672 7.808 42.696 ;
     RECT  7.189 43.824 7.808 44.424 ;
     RECT  7.808 2.148 7.912 45.372 ;
     RECT  7.912 2.418 8.104 45.102 ;
     RECT  8.104 5.76 8.165 5.784 ;
     RECT  8.104 29.616 8.165 29.64 ;
     RECT  8.104 43.824 8.165 44.136 ;
     RECT  8.104 20.928 9.065 20.952 ;
     RECT  8.104 28.224 9.133 28.248 ;
     RECT  9.097 29.28 9.133 29.304 ;
     RECT  9.133 28.224 9.281 29.304 ;
     RECT  8.104 23.376 9.317 23.4 ;
     RECT  9.281 28.224 9.353 28.248 ;
     RECT  9.421 14.928 9.457 14.952 ;
     RECT  9.925 43.104 9.961 43.128 ;
     RECT  8.104 8.208 10.508 8.808 ;
     RECT  9.457 14.928 10.508 15.048 ;
     RECT  10.501 21.456 10.508 21.48 ;
     RECT  9.529 22.704 10.508 22.728 ;
     RECT  8.104 26.304 10.508 26.328 ;
     RECT  9.281 29.28 10.508 29.304 ;
     RECT  9.385 34.32 10.508 34.344 ;
     RECT  8.104 35.424 10.508 38.76 ;
     RECT  9.961 42.48 10.508 43.128 ;
     RECT  8.165 44.112 10.508 44.136 ;
     RECT  10.508 2.148 10.612 45.372 ;
     RECT  10.612 2.148 10.804 45.102 ;
     RECT  10.804 32.208 10.829 32.232 ;
     RECT  10.804 20.88 11.045 20.904 ;
     RECT  9.601 1.152 11.113 1.176 ;
     RECT  10.804 2.148 11.113 2.904 ;
     RECT  10.804 25.152 11.333 25.176 ;
     RECT  10.804 22.896 11.765 22.92 ;
     RECT  10.804 28.128 11.909 28.248 ;
     RECT  11.909 28.128 11.945 28.152 ;
     RECT  11.113 1.152 12.409 2.904 ;
     RECT  10.804 4.128 12.409 4.152 ;
     RECT  10.804 7.632 12.733 9 ;
     RECT  12.409 1.152 12.805 4.152 ;
     RECT  10.804 5.184 12.805 5.208 ;
     RECT  10.804 42.48 12.805 43.128 ;
     RECT  10.804 44.112 12.805 44.136 ;
     RECT  12.805 1.152 13.208 5.208 ;
     RECT  12.733 7.632 13.208 9.336 ;
     RECT  12.805 11.712 13.208 11.736 ;
     RECT  12.445 14.832 13.208 14.856 ;
     RECT  12.481 16.32 13.208 16.344 ;
     RECT  12.661 22.704 13.208 22.728 ;
     RECT  13.013 25.68 13.208 26.04 ;
     RECT  10.804 35.424 13.208 38.76 ;
     RECT  12.805 39.744 13.208 39.768 ;
     RECT  10.804 40.896 13.208 40.92 ;
     RECT  12.805 42.48 13.208 44.136 ;
     RECT  13.208 1.152 13.312 45.372 ;
     RECT  13.312 1.152 13.504 45.102 ;
     RECT  5.941 0.048 13.921 0.072 ;
     RECT  13.504 1.152 13.921 5.208 ;
     RECT  13.504 35.424 14.533 39.768 ;
     RECT  13.504 40.896 14.533 43.128 ;
     RECT  13.504 7.488 14.569 9.24 ;
     RECT  13.921 0.048 14.785 5.208 ;
     RECT  14.605 6.336 14.785 6.36 ;
     RECT  14.785 0.048 15.041 6.36 ;
     RECT  15.041 0.144 15.145 6.36 ;
     RECT  14.569 7.488 15.145 9.816 ;
     RECT  15.145 0.144 15.257 9.816 ;
     RECT  15.181 33.12 15.397 33.144 ;
     RECT  14.929 22.8 15.577 22.824 ;
     RECT  13.504 44.112 15.749 44.136 ;
     RECT  15.781 46.752 15.905 46.776 ;
     RECT  15.257 0.864 15.908 9.816 ;
     RECT  13.504 11.712 15.908 11.736 ;
     RECT  15.289 15.552 15.908 15.576 ;
     RECT  13.504 17.136 15.908 17.16 ;
     RECT  14.785 20.304 15.908 20.328 ;
     RECT  14.713 21.456 15.908 21.48 ;
     RECT  15.577 22.8 15.908 23.208 ;
     RECT  13.504 24.624 15.908 24.648 ;
     RECT  13.504 29.328 15.908 29.352 ;
     RECT  15.397 32.256 15.908 33.144 ;
     RECT  14.533 35.424 15.908 43.128 ;
     RECT  15.749 44.112 15.908 45 ;
     RECT  15.908 0.864 16.012 45.372 ;
     RECT  16.012 0.864 16.204 45.102 ;
     RECT  16.204 22.848 16.445 23.64 ;
     RECT  16.204 25.776 17.201 27.144 ;
     RECT  16.204 24.624 17.269 24.648 ;
     RECT  17.201 25.776 17.269 26.328 ;
     RECT  16.204 16.512 17.593 17.16 ;
     RECT  16.445 23.616 17.593 23.64 ;
     RECT  17.269 24.624 17.593 26.328 ;
     RECT  16.204 35.424 17.593 43.128 ;
     RECT  16.204 0.864 17.701 9.816 ;
     RECT  17.593 16.512 17.845 17.736 ;
     RECT  16.204 18.96 17.845 18.984 ;
     RECT  16.204 32.256 17.881 33.144 ;
     RECT  16.204 20.304 17.989 20.328 ;
     RECT  16.204 21.456 17.989 21.48 ;
     RECT  16.204 29.328 18.241 29.352 ;
     RECT  17.881 31.968 18.241 33.144 ;
     RECT  17.701 0.864 18.313 10.632 ;
     RECT  16.204 11.712 18.313 11.736 ;
     RECT  17.845 16.512 18.529 18.984 ;
     RECT  18.313 0.864 18.608 11.736 ;
     RECT  18.205 13.68 18.608 13.704 ;
     RECT  17.593 14.928 18.608 14.952 ;
     RECT  18.529 16.512 18.608 19.032 ;
     RECT  17.989 20.304 18.608 21.48 ;
     RECT  17.593 23.616 18.608 26.328 ;
     RECT  18.241 29.328 18.608 29.88 ;
     RECT  18.241 31.968 18.608 33.864 ;
     RECT  17.593 34.992 18.608 43.128 ;
     RECT  18.608 0.864 18.712 45.372 ;
     RECT  18.712 0.864 18.904 45.102 ;
     RECT  18.904 0.864 19.897 21.48 ;
     RECT  18.904 22.464 19.897 43.128 ;
     RECT  19.897 0.864 21.157 43.128 ;
     RECT  21.157 0.72 21.409 43.128 ;
     RECT  21.409 0.72 21.564 43.224 ;
    LAYER M5 ;
     RECT  5.952 0.037 5.976 2.137 ;
     RECT  2.4 2.137 2.52 2.151 ;
     RECT  7.8 2.137 7.92 2.151 ;
     RECT  10.5 2.137 10.62 2.151 ;
     RECT  13.2 2.137 13.32 2.151 ;
     RECT  15.9 2.137 16.02 2.151 ;
     RECT  18.6 2.137 18.72 2.151 ;
     RECT  5.1 2.137 5.976 4.501 ;
     RECT  4.56 4.501 5.976 5.171 ;
     RECT  2.4 2.151 2.712 5.557 ;
     RECT  2.304 5.557 2.712 5.747 ;
     RECT  2.4 5.747 2.712 9.781 ;
     RECT  2.4 9.781 2.952 9.971 ;
     RECT  2.4 9.971 2.712 10.165 ;
     RECT  2.304 10.165 2.712 10.355 ;
     RECT  13.2 2.151 13.512 11.701 ;
     RECT  5.1 5.171 5.976 13.621 ;
     RECT  4.56 13.621 5.976 14.531 ;
     RECT  2.4 10.355 2.712 17.461 ;
     RECT  2.4 17.461 3.432 18.565 ;
     RECT  2.4 18.565 3.96 18.611 ;
     RECT  5.1 14.531 5.976 18.709 ;
     RECT  7.8 2.151 8.112 18.757 ;
     RECT  3.936 18.611 3.96 19.379 ;
     RECT  2.4 18.611 2.904 20.003 ;
     RECT  7.68 18.757 8.112 20.485 ;
     RECT  5.1 18.709 6.072 20.579 ;
     RECT  7.152 20.485 8.112 22.789 ;
     RECT  5.1 20.579 5.976 23.269 ;
     RECT  7.104 22.789 8.112 23.269 ;
     RECT  5.1 23.269 8.112 23.843 ;
     RECT  5.1 23.843 5.976 24.563 ;
     RECT  2.4 20.003 2.712 25.333 ;
     RECT  5.1 24.563 5.592 25.717 ;
     RECT  2.304 25.333 2.712 26.627 ;
     RECT  2.4 26.627 2.712 27.157 ;
     RECT  2.4 27.157 2.808 27.395 ;
     RECT  5.1 25.717 5.976 29.605 ;
     RECT  7.68 23.843 8.112 29.605 ;
     RECT  7.584 29.605 8.112 30.275 ;
     RECT  2.4 27.395 2.712 31.813 ;
     RECT  5.1 29.605 6.168 32.389 ;
     RECT  2.4 31.813 2.952 33.011 ;
     RECT  5.1 32.389 6.648 33.299 ;
     RECT  2.4 33.011 2.712 37.285 ;
     RECT  2.304 37.285 2.712 37.427 ;
     RECT  5.1 33.299 5.976 39.445 ;
     RECT  5.1 39.445 6.072 40.019 ;
     RECT  3.936 38.101 3.96 40.499 ;
     RECT  5.1 40.019 5.976 41.651 ;
     RECT  5.1 41.651 5.736 42.227 ;
     RECT  2.4 37.427 2.712 42.517 ;
     RECT  2.304 42.517 2.712 42.659 ;
     RECT  12.816 11.701 13.512 43.379 ;
     RECT  7.68 30.275 8.112 44.147 ;
     RECT  15.9 2.151 16.212 44.965 ;
     RECT  2.4 42.659 2.712 45.369 ;
     RECT  5.1 42.227 5.412 45.369 ;
     RECT  7.8 44.147 8.112 45.369 ;
     RECT  10.5 2.151 10.812 45.369 ;
     RECT  13.2 43.379 13.512 45.369 ;
     RECT  15.792 44.965 16.212 45.369 ;
     RECT  18.6 2.151 18.912 45.369 ;
     RECT  2.4 45.369 2.52 45.383 ;
     RECT  5.1 45.369 5.22 45.383 ;
     RECT  7.8 45.369 7.92 45.383 ;
     RECT  10.5 45.369 10.62 45.383 ;
     RECT  13.2 45.369 13.32 45.383 ;
     RECT  15.792 45.369 16.02 45.383 ;
     RECT  18.6 45.369 18.72 45.383 ;
     RECT  15.792 45.383 15.816 46.787 ;
  END
END qkd_rlysh_296
END LIBRARY
